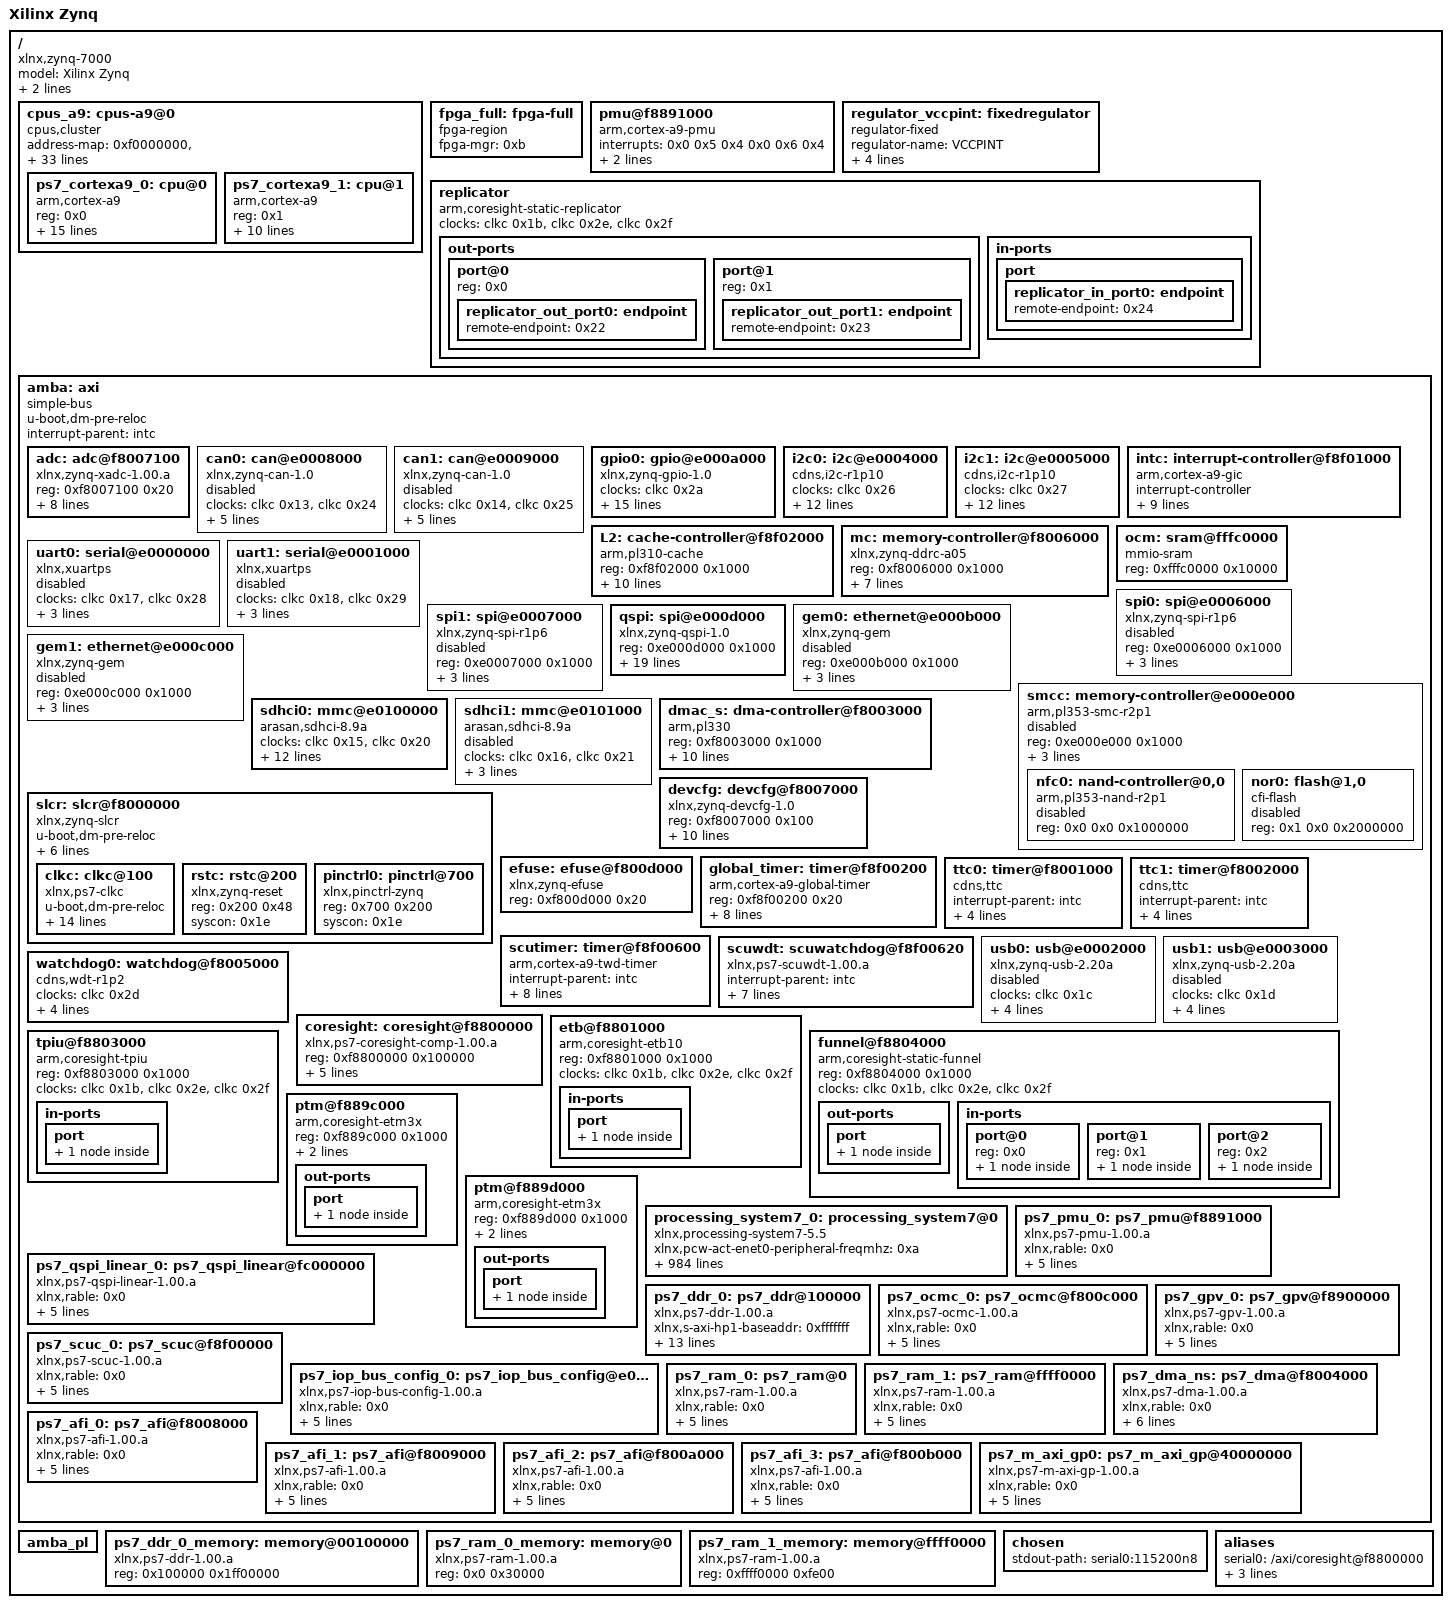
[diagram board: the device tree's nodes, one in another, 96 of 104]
/*
 * Copyright (C) 2011-2022 Xilinx, Inc.
 * Copyright (C) 2022 Advanced Micro Devices, Inc. All Rights Reserved.
 *
 * This software is licensed under the terms of the GNU General Public
 * License version 2, as published by the Free Software Foundation, and
 * may be copied, distributed, and modified under those terms.
 *
 * This program is distributed in the hope that it will be useful,
 * but WITHOUT ANY WARRANTY; without even the implied warranty of
 * MERCHANTABILITY or FITNESS FOR A PARTICULAR PURPOSE.  See the
 * GNU General Public License for more details.
 */

/dts-v1/;

/ {
        #address-cells = <0x1>;
        #size-cells = <0x1>;
        compatible = "xlnx,zynq-7000";
        model = "Xilinx Zynq";
        device_id = "7z010";
        slrcount = <0x1>;

        cpus_a9: cpus-a9@0 {
                #address-cells = <0x1>;
                #size-cells = <0x0>;
                compatible = "cpus,cluster";
                address-map = <0xf0000000 &amba 0xf0000000 0x10000000>,
                 <0x100000 &ps7_ddr_0_memory 0x100000 0x1ff00000>,
                 <0x0 &ps7_ram_0_memory 0x0 0x30000>,
                 <0xffff0000 &ps7_ram_1_memory 0xffff0000 0xfe00>,
                 <0xf8008000 &ps7_afi_0 0xf8008000 0x1000>,
                 <0xf8009000 &ps7_afi_1 0xf8009000 0x1000>,
                 <0xf800a000 &ps7_afi_2 0xf800a000 0x1000>,
                 <0xf800b000 &ps7_afi_3 0xf800b000 0x1000>,
                 <0xf8800000 &coresight 0xf8800000 0x100000>,
                 <0xf8006000 &mc 0xf8006000 0x1000>,
                 <0xf8007000 &devcfg 0xf8007000 0x100>,
                 <0xf8004000 &ps7_dma_ns 0xf8004000 0x1000>,
                 <0xf8003000 &dmac_s 0xf8003000 0x1000>,
                 <0xf8f00200 &global_timer 0xf8f00200 0x100>,
                 <0xe000a000 &gpio0 0xe000a000 0x1000>,
                 <0xf8900000 &ps7_gpv_0 0xf8900000 0x100000>,
                 <0xe0004000 &i2c0 0xe0004000 0x1000>,
                 <0xe0005000 &i2c1 0xe0005000 0x1000>,
                 <0xf8f01000 &intc 0xf8f01000 0x1000>,
                 <0xe0200000 &ps7_iop_bus_config_0 0xe0200000 0x1000>,
                 <0xf8f02000 &L2 0xf8f02000 0x1000>,
                 <0xf800c000 &ps7_ocmc_0 0xf800c000 0x1000>,
                 <0xf8891000 &ps7_pmu_0 0xf8891000 0x1000>,
                 <0xe000d000 &qspi 0xe000d000 0x1000>,
                 <0xfc000000 &ps7_qspi_linear_0 0xfc000000 0x1000000>,
                 <0xf8f00000 &ps7_scuc_0 0xf8f00000 0xfd>,
                 <0xf8f00600 &scutimer 0xf8f00600 0x20>,
                 <0xf8f00620 &scuwdt 0xf8f00620 0xe0>,
                 <0xe0100000 &sdhci0 0xe0100000 0x1000>,
                 <0xf8000000 &slcr 0xf8000000 0x1000>,
                 <0xf8007100 &adc 0xf8007100 0x21>;
                #ranges-address-cells = <0x1>;
                #ranges-size-cells = <0x1>;
                phandle = <0x2e>;

                ps7_cortexa9_0: cpu@0 {
                        compatible = "arm,cortex-a9";
                        device_type = "cpu";
                        reg = <0x0>;
                        clocks = <&clkc 0x3>;
                        clock-latency = <0x3e8>;
                        cpu0-supply = <0x21>;
                        operating-points = <0xa2c2b 0xf4240 0x51616 0xf4240>;
                        xlnx,rable = <0x0>;
                        xlnx,i-cache-size = <0x8000>;
                        xlnx,d-cache-line-size = <0x14>;
                        xlnx,i-cache-line-size = <0x14>;
                        xlnx,cpu-1x-clk-freq-hz = <0x69f6bcb>;
                        xlnx,ip-name = "ps7_cortexa9";
                        xlnx,num-cores = <0x2>;
                        xlnx,d-cache-size = <0x8000>;
                        xlnx,cpu-clk-freq-hz = <0x27bc86bf>;
                        bus-handle = <0x1>;
                        phandle = <0x2a>;
                };

                ps7_cortexa9_1: cpu@1 {
                        compatible = "arm,cortex-a9";
                        device_type = "cpu";
                        reg = <0x1>;
                        clocks = <&clkc 0x3>;
                        xlnx,rable = <0x0>;
                        xlnx,i-cache-size = <0x8000>;
                        xlnx,d-cache-line-size = <0x14>;
                        xlnx,i-cache-line-size = <0x14>;
                        xlnx,cpu-1x-clk-freq-hz = <0x69f6bcb>;
                        xlnx,ip-name = "ps7_cortexa9";
                        xlnx,d-cache-size = <0x8000>;
                        xlnx,cpu-clk-freq-hz = <0x27bc86bf>;
                        bus-handle = <0x1>;
                        phandle = <0x2c>;
                };
        };

        fpga_full: fpga-full {
                compatible = "fpga-region";
                fpga-mgr = <0xb>;
                #address-cells = <0x1>;
                #size-cells = <0x1>;
                ranges;
                phandle = <0x2f>;
        };

        pmu@f8891000 {
                compatible = "arm,cortex-a9-pmu";
                interrupts = <0x0 0x5 0x4 0x0 0x6 0x4>;
                interrupt-parent = <&intc>;
                reg = <0xf8891000 0x1000 0xf8893000 0x1000>;
        };

        regulator_vccpint: fixedregulator {
                compatible = "regulator-fixed";
                regulator-name = "VCCPINT";
                regulator-min-microvolt = <0xf4240>;
                regulator-max-microvolt = <0xf4240>;
                regulator-boot-on;
                regulator-always-on;
                phandle = <0x21>;
        };

        replicator {
                compatible = "arm,coresight-static-replicator";
                clocks = <&clkc 0x1b>,
                 <&clkc 0x2e>,
                 <&clkc 0x2f>;
                clock-names = "apb_pclk", "dbg_trc", "dbg_apb";

                out-ports {
                        #address-cells = <0x1>;
                        #size-cells = <0x0>;
                        /* replicator output ports */

                        port@0 {
                                reg = <0x0>;

                                replicator_out_port0: endpoint {
                                        remote-endpoint = <0x22>;
                                        phandle = <0x26>;
                                };
                        };

                        port@1 {
                                reg = <0x1>;

                                replicator_out_port1: endpoint {
                                        remote-endpoint = <0x23>;
                                        phandle = <0x25>;
                                };
                        };
                };

                in-ports {
                        /* replicator input port */

                        port {

                                replicator_in_port0: endpoint {
                                        remote-endpoint = <0x24>;
                                        phandle = <0x27>;
                                };
                        };
                };
        };

        amba: axi {
                u-boot,dm-pre-reloc;
                compatible = "simple-bus";
                #address-cells = <0x1>;
                #size-cells = <0x1>;
                interrupt-parent = <&intc>;
                ranges;
                phandle = <0x1>;

                adc: adc@f8007100 {
                        compatible = "xlnx,zynq-xadc-1.00.a";
                        reg = <0xf8007100 0x20>;
                        interrupts = <0x0 0x7 0x4>;
                        interrupt-parent = <&intc>;
                        clocks = <&clkc 0xc>;
                        xlnx,rable = <0x0>;
                        status = "okay";
                        xlnx,interconnect-s-axi-masters = "ps7_cortexa9_0.M_AXI_DP , & , ps7_cortexa9_1.M_AXI_DP";
                        xlnx,ip-name = "ps7_xadc";
                        xlnx,name = "ps7_xadc_0";
                        phandle = <0x1f>;
                };

                can0: can@e0008000 {
                        compatible = "xlnx,zynq-can-1.0";
                        status = "disabled";
                        clocks = <&clkc 0x13>,
                         <&clkc 0x24>;
                        clock-names = "can_clk", "pclk";
                        reg = <0xe0008000 0x1000>;
                        interrupts = <0x0 0x1c 0x4>;
                        interrupt-parent = <&intc>;
                        tx-fifo-depth = <0x40>;
                        rx-fifo-depth = <0x40>;
                        phandle = <0x30>;
                };

                can1: can@e0009000 {
                        compatible = "xlnx,zynq-can-1.0";
                        status = "disabled";
                        clocks = <&clkc 0x14>,
                         <&clkc 0x25>;
                        clock-names = "can_clk", "pclk";
                        reg = <0xe0009000 0x1000>;
                        interrupts = <0x0 0x33 0x4>;
                        interrupt-parent = <&intc>;
                        tx-fifo-depth = <0x40>;
                        rx-fifo-depth = <0x40>;
                        phandle = <0x31>;
                };

                gpio0: gpio@e000a000 {
                        compatible = "xlnx,zynq-gpio-1.0";
                        #gpio-cells = <0x2>;
                        clocks = <&clkc 0x2a>;
                        gpio-controller;
                        interrupt-controller;
                        #interrupt-cells = <0x2>;
                        interrupt-parent = <&intc>;
                        interrupts = <0x0 0x14 0x4>;
                        reg = <0xe000a000 0x1000>;
                        xlnx,rable = <0x0>;
                        xlnx,mio-gpio-mask = <0x5600>;
                        status = "okay";
                        gpio-mask-high = <0x0>;
                        xlnx,interconnect-s-axi-masters = "ps7_cortexa9_0.M_AXI_DP , & , ps7_cortexa9_1.M_AXI_DP";
                        xlnx,emio-gpio-width = <0x40>;
                        xlnx,ip-name = "ps7_gpio";
                        gpio-mask-low = <0x5600>;
                        emio-gpio-width = <0x40>;
                        xlnx,name = "ps7_gpio_0";
                        phandle = <0xf>;
                };

                i2c0: i2c@e0004000 {
                        compatible = "cdns,i2c-r1p10";
                        status = "okay";
                        clocks = <&clkc 0x26>;
                        clock-frequency = <0x61a80>;
                        interrupt-parent = <&intc>;
                        interrupts = <0x0 0x19 0x4>;
                        reg = <0xe0004000 0x1000>;
                        #address-cells = <0x1>;
                        #size-cells = <0x0>;
                        xlnx,rable = <0x0>;
                        xlnx,has-interrupt = <0x0>;
                        xlnx,clock-freq = <0x69f6bcb>;
                        xlnx,interconnect-s-axi-masters = "ps7_cortexa9_0.M_AXI_DP , & , ps7_cortexa9_1.M_AXI_DP";
                        xlnx,i2c-clk-freq-hz = <0x69f6bcb>;
                        xlnx,ip-name = "ps7_i2c";
                        xlnx,name = "ps7_i2c_0";
                        phandle = <0x11>;
                };

                i2c1: i2c@e0005000 {
                        compatible = "cdns,i2c-r1p10";
                        status = "okay";
                        clocks = <&clkc 0x27>;
                        clock-frequency = <0x61a80>;
                        interrupt-parent = <&intc>;
                        interrupts = <0x0 0x30 0x4>;
                        reg = <0xe0005000 0x1000>;
                        #address-cells = <0x1>;
                        #size-cells = <0x0>;
                        xlnx,rable = <0x0>;
                        xlnx,has-interrupt = <0x0>;
                        xlnx,clock-freq = <0x69f6bcb>;
                        xlnx,interconnect-s-axi-masters = "ps7_cortexa9_0.M_AXI_DP , & , ps7_cortexa9_1.M_AXI_DP";
                        xlnx,i2c-clk-freq-hz = <0x69f6bcb>;
                        xlnx,ip-name = "ps7_i2c";
                        xlnx,name = "ps7_i2c_1";
                        phandle = <0x12>;
                };

                intc: interrupt-controller@f8f01000 {
                        compatible = "arm,cortex-a9-gic";
                        #interrupt-cells = <0x3>;
                        interrupt-controller;
                        reg = <0xf8f01000 0x1000 0xf8f00100 0x100>;
                        xlnx,rable = <0x0>;
                        status = "okay";
                        xlnx,ppi-s-axi-baseaddr = <0xf8f01000>;
                        xlnx,irq-f2p-mode = "DIRECT";
                        xlnx,interconnect-s-axi-masters = "ps7_cortexa9_0.M_AXI_DP , & , ps7_cortexa9_1.M_AXI_DP";
                        xlnx,ip-name = "ps7_intc_dist";
                        xlnx,ppi-s-axi-highaddr = <0xf8f01fff>;
                        xlnx,name = "ps7_intc_dist_0";
                        phandle = <0x13>;
                };

                L2: cache-controller@f8f02000 {
                        compatible = "arm,pl310-cache";
                        reg = <0xf8f02000 0x1000>;
                        interrupts = <0x0 0x2 0x4>;
                        arm,data-latency = <0x3 0x2 0x2>;
                        arm,tag-latency = <0x2 0x2 0x2>;
                        cache-unified;
                        cache-level = <0x2>;
                        xlnx,rable = <0x0>;
                        status = "okay";
                        xlnx,interconnect-s-axi-masters = "ps7_cortexa9_0.M_AXI_DP , & , ps7_cortexa9_1.M_AXI_DP";
                        xlnx,ip-name = "ps7_pl310";
                        xlnx,name = "ps7_pl310_0";
                        phandle = <0x15>;
                };

                mc: memory-controller@f8006000 {
                        compatible = "xlnx,zynq-ddrc-a05";
                        reg = <0xf8006000 0x1000>;
                        xlnx,rable = <0x0>;
                        status = "okay";
                        xlnx,interconnect-s-axi-masters = "ps7_cortexa9_0.M_AXI_DP , & , ps7_cortexa9_1.M_AXI_DP";
                        xlnx,ddr-clk-freq-hz = <0x1fca057e>;
                        xlnx,ip-name = "ps7_ddrc";
                        xlnx,has-ecc = <0x0>;
                        xlnx,name = "ps7_ddrc_0";
                        phandle = <0xa>;
                };

                ocm: sram@fffc0000 {
                        compatible = "mmio-sram";
                        reg = <0xfffc0000 0x10000>;
                        phandle = <0x32>;
                };

                uart0: serial@e0000000 {
                        compatible = "xlnx,xuartps", "cdns,uart-r1p8";
                        status = "disabled";
                        clocks = <&clkc 0x17>,
                         <&clkc 0x28>;
                        clock-names = "uart_clk", "pclk";
                        reg = <0xe0000000 0x1000>;
                        interrupts = <0x0 0x1b 0x4>;
                        interrupt-parent = <&intc>;
                        phandle = <0x33>;
                };

                uart1: serial@e0001000 {
                        compatible = "xlnx,xuartps", "cdns,uart-r1p8";
                        status = "disabled";
                        clocks = <&clkc 0x18>,
                         <&clkc 0x29>;
                        clock-names = "uart_clk", "pclk";
                        reg = <0xe0001000 0x1000>;
                        interrupts = <0x0 0x32 0x4>;
                        interrupt-parent = <&intc>;
                        phandle = <0x34>;
                };

                spi0: spi@e0006000 {
                        compatible = "xlnx,zynq-spi-r1p6";
                        reg = <0xe0006000 0x1000>;
                        status = "disabled";
                        interrupt-parent = <&intc>;
                        interrupts = <0x0 0x1a 0x4>;
                        clocks = <&clkc 0x19>,
                         <&clkc 0x22>;
                        clock-names = "ref_clk", "pclk";
                        #address-cells = <0x1>;
                        #size-cells = <0x0>;
                        phandle = <0x35>;
                };

                spi1: spi@e0007000 {
                        compatible = "xlnx,zynq-spi-r1p6";
                        reg = <0xe0007000 0x1000>;
                        status = "disabled";
                        interrupt-parent = <&intc>;
                        interrupts = <0x0 0x31 0x4>;
                        clocks = <&clkc 0x1a>,
                         <&clkc 0x23>;
                        clock-names = "ref_clk", "pclk";
                        #address-cells = <0x1>;
                        #size-cells = <0x0>;
                        phandle = <0x36>;
                };

                qspi: spi@e000d000 {
                        compatible = "xlnx,zynq-qspi-1.0";
                        reg = <0xe000d000 0x1000>;
                        interrupt-parent = <&intc>;
                        interrupts = <0x0 0x13 0x4>;
                        clocks = <&clkc 0xa>,
                         <&clkc 0x2b>;
                        clock-names = "ref_clk", "pclk";
                        status = "okay";
                        #address-cells = <0x1>;
                        #size-cells = <0x0>;
                        xlnx,qspi-clk-freq-hz = <0xbebc200>;
                        xlnx,rable = <0x0>;
                        xlnx,bus-width = <0x2>;
                        xlnx,ip-name = "ps7_qspi";
                        xlnx,interconnect-s-axi-masters = "ps7_cortexa9_0.M_AXI_DP , & , ps7_cortexa9_1.M_AXI_DP";
                        spi-rx-bus-width = <0x4>;
                        xlnx,connection-mode = <0x0>;
                        spi-tx-bus-width = <0x4>;
                        qspi-fbclk = <0x0>;
                        xlnx,clock-freq = <0xbebc200>;
                        xlnx,fb-clk = <0x0>;
                        xlnx,qspi-mode = <0x0>;
                        xlnx,name = "ps7_qspi_0";
                        xlnx,qspi-bus-width = <0x2>;
                        is-dual = <0x0>;
                        phandle = <0x18>;
                };

                gem0: ethernet@e000b000 {
                        compatible = "xlnx,zynq-gem", "cdns,gem";
                        reg = <0xe000b000 0x1000>;
                        status = "disabled";
                        interrupts = <0x0 0x16 0x4>;
                        interrupt-parent = <&intc>;
                        clocks = <&clkc 0x1e>,
                         <&clkc 0x1e>,
                         <&clkc 0xd>;
                        clock-names = "pclk", "hclk", "tx_clk";
                        #address-cells = <0x1>;
                        #size-cells = <0x0>;
                        phandle = <0x37>;
                };

                gem1: ethernet@e000c000 {
                        compatible = "xlnx,zynq-gem", "cdns,gem";
                        reg = <0xe000c000 0x1000>;
                        status = "disabled";
                        interrupts = <0x0 0x2d 0x4>;
                        interrupt-parent = <&intc>;
                        clocks = <&clkc 0x1f>,
                         <&clkc 0x1f>,
                         <&clkc 0xe>;
                        clock-names = "pclk", "hclk", "tx_clk";
                        #address-cells = <0x1>;
                        #size-cells = <0x0>;
                        phandle = <0x38>;
                };

                smcc: memory-controller@e000e000 {
                        compatible = "arm,pl353-smc-r2p1", "arm,primecell";
                        reg = <0xe000e000 0x1000>;
                        status = "disabled";
                        clock-names = "memclk", "apb_pclk";
                        clocks = <&clkc 0xb>,
                         <&clkc 0x2c>;
                        ranges = <0x0 0x0 0xe1000000 0x1000000 0x1 0x0 0xe2000000 0x2000000 0x2 0x0 0xe4000000 0x2000000>;
                        /* SRAM/NOR CS1 region */
                        #address-cells = <0x2>;
                        #size-cells = <0x1>;
                        interrupt-parent = <&intc>;
                        interrupts = <0x0 0x12 0x4>;
                        phandle = <0x39>;

                        nfc0: nand-controller@0,0 {
                                compatible = "arm,pl353-nand-r2p1";
                                reg = <0x0 0x0 0x1000000>;
                                status = "disabled";
                                #address-cells = <0x1>;
                                #size-cells = <0x0>;
                                phandle = <0x3a>;
                        };

                        nor0: flash@1,0 {
                                status = "disabled";
                                compatible = "cfi-flash";
                                reg = <0x1 0x0 0x2000000>;
                                #address-cells = <0x1>;
                                #size-cells = <0x1>;
                                phandle = <0x3b>;
                        };
                };

                sdhci0: mmc@e0100000 {
                        compatible = "arasan,sdhci-8.9a";
                        status = "okay";
                        clock-names = "clk_xin", "clk_ahb";
                        clocks = <&clkc 0x15>,
                         <&clkc 0x20>;
                        interrupt-parent = <&intc>;
                        interrupts = <0x0 0x18 0x4>;
                        reg = <0xe0100000 0x1000>;
                        xlnx,rable = <0x0>;
                        xlnx,has-power = <0x0>;
                        xlnx,interconnect-s-axi-masters = "ps7_cortexa9_0.M_AXI_DP , & , ps7_cortexa9_1.M_AXI_DP";
                        xlnx,ip-name = "ps7_sdio";
                        xlnx,sdio-clk-freq-hz = <0x5f5e100>;
                        xlnx,has-wp = <0x0>;
                        xlnx,has-cd = <0x0>;
                        xlnx,name = "ps7_sd_0";
                        phandle = <0x1d>;
                };

                sdhci1: mmc@e0101000 {
                        compatible = "arasan,sdhci-8.9a";
                        status = "disabled";
                        clock-names = "clk_xin", "clk_ahb";
                        clocks = <&clkc 0x16>,
                         <&clkc 0x21>;
                        interrupt-parent = <&intc>;
                        interrupts = <0x0 0x2f 0x4>;
                        reg = <0xe0101000 0x1000>;
                        phandle = <0x3c>;
                };

                slcr: slcr@f8000000 {
                        u-boot,dm-pre-reloc;
                        #address-cells = <0x1>;
                        #size-cells = <0x1>;
                        compatible = "xlnx,zynq-slcr", "syscon", "simple-mfd";
                        reg = <0xf8000000 0x1000>;
                        ranges;
                        xlnx,rable = <0x0>;
                        status = "okay";
                        xlnx,interconnect-s-axi-masters = "ps7_cortexa9_0.M_AXI_DP , & , ps7_cortexa9_1.M_AXI_DP";
                        xlnx,ip-name = "ps7_slcr";
                        xlnx,name = "ps7_slcr_0";
                        phandle = <0x1e>;

                        clkc: clkc@100 {
                                u-boot,dm-pre-reloc;
                                #clock-cells = <0x1>;
                                compatible = "xlnx,ps7-clkc";
                                fclk-enable = <0x1>;
                                clock-output-names = "armpll", "ddrpll", "iopll", "cpu_6or4x", "cpu_3or2x", "cpu_2x", "cpu_1x", "ddr2x", "ddr3x", "dci", "lqspi", "smc", "pcap", "gem0", "gem1", "fclk0", "fclk1", "fclk2", "fclk3", "can0", "can1", "sdio0", "sdio1", "uart0", "uart1", "spi0", "spi1", "dma", "usb0_aper", "usb1_aper", "gem0_aper", "gem1_aper", "sdio0_aper", "sdio1_aper", "spi0_aper", "spi1_aper", "can0_aper", "can1_aper", "i2c0_aper", "i2c1_aper", "uart0_aper", "uart1_aper", "gpio_aper", "lqspi_aper", "smc_aper", "swdt", "dbg_trc", "dbg_apb";
                                reg = <0x100 0x100>;
                                ps-clk-frequency = <0x1fca055>;
                                phandle = <0x20>;
                        };

                        rstc: rstc@200 {
                                compatible = "xlnx,zynq-reset";
                                reg = <0x200 0x48>;
                                #reset-cells = <0x1>;
                                syscon = <0x1e>;
                                phandle = <0x3d>;
                        };

                        pinctrl0: pinctrl@700 {
                                compatible = "xlnx,pinctrl-zynq";
                                reg = <0x700 0x200>;
                                syscon = <0x1e>;
                                phandle = <0x3e>;
                        };
                };

                dmac_s: dma-controller@f8003000 {
                        compatible = "arm,pl330", "arm,primecell";
                        reg = <0xf8003000 0x1000>;
                        interrupt-parent = <&intc>;
                        /*
                         * interrupt-names = "abort", "dma0", "dma1", "dma2", "dma3",
                         * "dma4", "dma5", "dma6", "dma7";
                         */
                        interrupts = <0x0 0xd 0x4 0x0 0xe 0x4 0x0 0xf 0x4 0x0 0x10 0x4 0x0 0x11 0x4 0x0 0x28 0x4 0x0 0x29 0x4 0x0 0x2a 0x4 0x0 0x2b 0x4>;
                        #dma-cells = <0x1>;
                        clocks = <&clkc 0x1b>;
                        clock-names = "apb_pclk";
                        xlnx,rable = <0x0>;
                        status = "okay";
                        xlnx,interconnect-s-axi-masters = "ps7_cortexa9_0.M_AXI_DP , & , ps7_cortexa9_1.M_AXI_DP";
                        xlnx,ip-name = "ps7_dma";
                        xlnx,is-secure;
                        xlnx,name = "ps7_dma_s";
                        phandle = <0xd>;
                };

                devcfg: devcfg@f8007000 {
                        compatible = "xlnx,zynq-devcfg-1.0";
                        reg = <0xf8007000 0x100>;
                        interrupt-parent = <&intc>;
                        interrupts = <0x0 0x8 0x4>;
                        clocks = <&clkc 0xc>,
                         <&clkc 0xf>,
                         <&clkc 0x10>,
                         <&clkc 0x11>,
                         <&clkc 0x12>;
                        clock-names = "ref_clk", "fclk0", "fclk1", "fclk2", "fclk3";
                        syscon = <0x1e>;
                        xlnx,rable = <0x0>;
                        status = "okay";
                        xlnx,interconnect-s-axi-masters = "ps7_cortexa9_0.M_AXI_DP , & , ps7_cortexa9_1.M_AXI_DP";
                        xlnx,ip-name = "ps7_dev_cfg";
                        xlnx,name = "ps7_dev_cfg_0";
                        phandle = <0xb>;
                };

                efuse: efuse@f800d000 {
                        compatible = "xlnx,zynq-efuse";
                        reg = <0xf800d000 0x20>;
                        phandle = <0x3f>;
                };

                global_timer: timer@f8f00200 {
                        compatible = "arm,cortex-a9-global-timer";
                        reg = <0xf8f00200 0x20>;
                        interrupts = <0x1 0xb 0x301>;
                        interrupt-parent = <&intc>;
                        clocks = <&clkc 0x4>;
                        xlnx,rable = <0x0>;
                        status = "okay";
                        xlnx,interconnect-s-axi-masters = "ps7_cortexa9_0.M_AXI_DP , & , ps7_cortexa9_1.M_AXI_DP";
                        xlnx,ip-name = "ps7_globaltimer";
                        xlnx,name = "ps7_globaltimer_0";
                        phandle = <0xe>;
                };

                ttc0: timer@f8001000 {
                        interrupt-parent = <&intc>;
                        interrupts = <0x0 0xa 0x4 0x0 0xb 0x4 0x0 0xc 0x4>;
                        compatible = "cdns,ttc";
                        clocks = <&clkc 0x6>;
                        reg = <0xf8001000 0x1000>;
                        phandle = <0x40>;
                };

                ttc1: timer@f8002000 {
                        interrupt-parent = <&intc>;
                        interrupts = <0x0 0x25 0x4 0x0 0x26 0x4 0x0 0x27 0x4>;
                        compatible = "cdns,ttc";
                        clocks = <&clkc 0x6>;
                        reg = <0xf8002000 0x1000>;
                        phandle = <0x41>;
                };

                scutimer: timer@f8f00600 {
                        interrupt-parent = <&intc>;
                        interrupts = <0x1 0xd 0x301>;
                        compatible = "arm,cortex-a9-twd-timer";
                        reg = <0xf8f00600 0x20>;
                        clocks = <&clkc 0x4>;
                        xlnx,rable = <0x0>;
                        status = "okay";
                        xlnx,interconnect-s-axi-masters = "ps7_cortexa9_0.M_AXI_DP , & , ps7_cortexa9_1.M_AXI_DP";
                        xlnx,ip-name = "ps7_scutimer";
                        xlnx,name = "ps7_scutimer_0";
                        phandle = <0x1b>;
                };

                scuwdt: scuwatchdog@f8f00620 {
                        interrupt-parent = <&intc>;
                        interrupts = <0x1 0xe 0x4>;
                        compatible = "xlnx,ps7-scuwdt-1.00.a";
                        reg = <0xf8f00620 0xe0>;
                        xlnx,rable = <0x0>;
                        status = "okay";
                        xlnx,interconnect-s-axi-masters = "ps7_cortexa9_0.M_AXI_DP , & , ps7_cortexa9_1.M_AXI_DP";
                        xlnx,ip-name = "ps7_scuwdt";
                        xlnx,name = "ps7_scuwdt_0";
                        phandle = <0x1c>;
                };

                usb0: usb@e0002000 {
                        compatible = "xlnx,zynq-usb-2.20a", "chipidea,usb2";
                        status = "disabled";
                        clocks = <&clkc 0x1c>;
                        interrupt-parent = <&intc>;
                        interrupts = <0x0 0x15 0x4>;
                        reg = <0xe0002000 0x1000>;
                        phy_type = "ulpi";
                        phandle = <0x42>;
                };

                usb1: usb@e0003000 {
                        compatible = "xlnx,zynq-usb-2.20a", "chipidea,usb2";
                        status = "disabled";
                        clocks = <&clkc 0x1d>;
                        interrupt-parent = <&intc>;
                        interrupts = <0x0 0x2c 0x4>;
                        reg = <0xe0003000 0x1000>;
                        phy_type = "ulpi";
                        phandle = <0x43>;
                };

                watchdog0: watchdog@f8005000 {
                        clocks = <&clkc 0x2d>;
                        compatible = "cdns,wdt-r1p2";
                        interrupt-parent = <&intc>;
                        interrupts = <0x0 0x9 0x1>;
                        reg = <0xf8005000 0x1000>;
                        timeout-sec = <0xa>;
                        phandle = <0x44>;
                };

                coresight: coresight@f8800000 {
                        compatible = "xlnx,ps7-coresight-comp-1.00.a";
                        status = "okay";
                        reg = <0xf8800000 0x100000>;
                        xlnx,rable = <0x0>;
                        xlnx,interconnect-s-axi-masters = "ps7_cortexa9_0.M_AXI_DP , & , ps7_cortexa9_1.M_AXI_DP";
                        xlnx,ip-name = "ps7_coresight_comp";
                        xlnx,name = "ps7_coresight_comp_0";
                        phandle = <0x9>;
                };

                etb@f8801000 {
                        compatible = "arm,coresight-etb10", "arm,primecell";
                        reg = <0xf8801000 0x1000>;
                        clocks = <&clkc 0x1b>,
                         <&clkc 0x2e>,
                         <&clkc 0x2f>;
                        clock-names = "apb_pclk", "dbg_trc", "dbg_apb";

                        in-ports {

                                port {

                                        etb_in_port: endpoint {
                                                remote-endpoint = <0x25>;
                                                phandle = <0x23>;
                                        };
                                };
                        };
                };

                tpiu@f8803000 {
                        compatible = "arm,coresight-tpiu", "arm,primecell";
                        reg = <0xf8803000 0x1000>;
                        clocks = <&clkc 0x1b>,
                         <&clkc 0x2e>,
                         <&clkc 0x2f>;
                        clock-names = "apb_pclk", "dbg_trc", "dbg_apb";

                        in-ports {

                                port {

                                        tpiu_in_port: endpoint {
                                                remote-endpoint = <0x26>;
                                                phandle = <0x22>;
                                        };
                                };
                        };
                };

                funnel@f8804000 {
                        compatible = "arm,coresight-static-funnel", "arm,primecell";
                        reg = <0xf8804000 0x1000>;
                        clocks = <&clkc 0x1b>,
                         <&clkc 0x2e>,
                         <&clkc 0x2f>;
                        clock-names = "apb_pclk", "dbg_trc", "dbg_apb";
                        /* funnel output ports */

                        out-ports {

                                port {

                                        funnel_out_port: endpoint {
                                                remote-endpoint = <0x27>;
                                                phandle = <0x24>;
                                        };
                                };
                        };

                        in-ports {
                                #address-cells = <0x1>;
                                #size-cells = <0x0>;
                                /* funnel input ports */

                                port@0 {
                                        reg = <0x0>;

                                        funnel0_in_port0: endpoint {
                                                remote-endpoint = <0x28>;
                                                phandle = <0x2b>;
                                        };
                                };

                                port@1 {
                                        reg = <0x1>;

                                        funnel0_in_port1: endpoint {
                                                remote-endpoint = <0x29>;
                                                phandle = <0x2d>;
                                        };
                                };

                                port@2 {
                                        reg = <0x2>;

                                        funnel0_in_port2: endpoint {
                                                phandle = <0x45>;
                                        };
                                };
                        };
                };

                ptm@f889c000 {
                        compatible = "arm,coresight-etm3x", "arm,primecell";
                        reg = <0xf889c000 0x1000>;
                        clocks = <&clkc 0x1b>,
                         <&clkc 0x2e>,
                         <&clkc 0x2f>;
                        clock-names = "apb_pclk", "dbg_trc", "dbg_apb";
                        cpu = <0x2a>;

                        out-ports {

                                port {

                                        ptm0_out_port: endpoint {
                                                remote-endpoint = <0x2b>;
                                                phandle = <0x28>;
                                        };
                                };
                        };
                };

                ptm@f889d000 {
                        compatible = "arm,coresight-etm3x", "arm,primecell";
                        reg = <0xf889d000 0x1000>;
                        clocks = <&clkc 0x1b>,
                         <&clkc 0x2e>,
                         <&clkc 0x2f>;
                        clock-names = "apb_pclk", "dbg_trc", "dbg_apb";
                        cpu = <0x2c>;

                        out-ports {

                                port {

                                        ptm1_out_port: endpoint {
                                                remote-endpoint = <0x2d>;
                                                phandle = <0x29>;
                                        };
                                };
                        };
                };

                processing_system7_0: processing_system7@0 {
                        xlnx,pcw-act-enet0-peripheral-freqmhz = <0xa>;
                        xlnx,pcw-nor-grp-sram-cs1-io = "<Select>";
                        xlnx,num-f2p-intr-inputs = <0x1>;
                        reg = <0x0 0x20000000>;
                        xlnx,pcw-mio-18-direction = "inout";
                        xlnx,pcw-nand-cycles-t-ar = <0x1>;
                        xlnx,pcw-p2f-dmac7-intr = <0x0>;
                        xlnx,pcw-en-clk1-port = <0x1>;
                        xlnx,pcw-crystal-peripheral-freqmhz = <0x1fca055>;
                        xlnx,pcw-nor-grp-sram-cs1-enable = <0x0>;
                        xlnx,pcw-uiparam-ddr-dq-1-package-length = <0x4366e20>;
                        xlnx,pcw-act-wdt-peripheral-freqmhz = <0x69f6bcb>;
                        xlnx,pcw-p2f-dmac4-intr = <0x0>;
                        xlnx,pcw-s-axi-hp3-id-width = <0x6>;
                        xlnx,pcw-en-emio-uart0 = <0x0>;
                        xlnx,pcw-en-emio-uart1 = <0x0>;
                        xlnx,pcw-ddr-hpr-to-critical-priority-level = <0xf>;
                        xlnx,pcw-enet-reset-polarity = "Active , Low";
                        xlnx,pcw-mio-5-direction = "inout";
                        xlnx,pcw-p2f-dmac1-intr = <0x0>;
                        xlnx,pcw-sd0-grp-cd-enable = <0x0>;
                        xlnx,pcw-act-fpga1-peripheral-freqmhz = <0x20>;
                        xlnx,pcw-mio-24-iotype = "LVCMOS , 3.3V";
                        xlnx,pcw-ddr-port1-hpr-enable = <0x0>;
                        xlnx,pcw-cpu-peripheral-clksrc = "ARM , PLL";
                        xlnx,pcw-mio-53-pullup = "enabled";
                        xlnx,pcw-use-axi-nonsecure = <0x0>;
                        xlnx,pcw-spi1-grp-ss0-io = "<Select>";
                        xlnx,pcw-uiparam-ddr-dqs-1-propogation-delay = <0xa0>;
                        xlnx,pcw-nor-cs1-t-pc = <0x1>;
                        xlnx,pcw-s-axi-gp0-id-width = <0x6>;
                        xlnx,pcw-trace-grp-8bit-io = "<Select>";
                        xlnx,pcw-ttc-peripheral-freqmhz = <0x32>;
                        xlnx,pcw-uart0-baseaddr = <0xe0000000>;
                        xlnx,pcw-ftm-cti-out0 = "DISABLED";
                        xlnx,pcw-ttc1-clk0-peripheral-divisor0 = <0x1>;
                        xlnx,pcw-uiparam-ddr-clock-stop-en = <0x0>;
                        xlnx,pcw-ftm-cti-out1 = "DISABLED";
                        xlnx,pcw-mio-28-direction = "inout";
                        xlnx,pcw-en-ttc0 = <0x0>;
                        xlnx,pcw-ftm-cti-out2 = "DISABLED";
                        xlnx,pcw-mio-11-pullup = "enabled";
                        xlnx,pcw-en-ttc1 = <0x0>;
                        xlnx,pcw-ftm-cti-out3 = "DISABLED";
                        xlnx,pcw-m-axi-gp0-thread-id-width = <0xc>;
                        xlnx,pcw-nor-sram-cs1-t-ceoe = <0x1>;
                        xlnx,pcw-nor-grp-sram-int-enable = <0x0>;
                        xlnx,pcw-can-peripheral-clksrc = "IO , PLL";
                        xlnx,pcw-ttc1-clk0-peripheral-clksrc = "CPU_1X";
                        xlnx,mio-primitive = <0x36>;
                        xlnx,pcw-gp0-num-write-threads = <0x4>;
                        xlnx,pcw-mio-4-iotype = "LVCMOS , 3.3V";
                        xlnx,pcw-mio-41-iotype = "LVCMOS , 3.3V";
                        xlnx,pcw-nor-cs1-t-rc = <0xb>;
                        xlnx,pcw-i2c0-grp-int-enable = <0x0>;
                        xlnx,pcw-ddr-port2-hpr-enable = <0x0>;
                        xlnx,pcw-act-tpiu-peripheral-freqmhz = <0xc8>;
                        xlnx,pcw-package-name = "clg400";
                        xlnx,pcw-s-axi-hp0-id-width = <0x6>;
                        xlnx,pcw-package-ddr-dqs-to-clk-delay-0 = <0x153d8>;
                        xlnx,pcw-uiparam-ddr-dqs-3-length-mm = <0x0>;
                        xlnx,pcw-package-ddr-dqs-to-clk-delay-1 = <0x29810>;
                        xlnx,pcw-qspi-grp-single-ss-enable = <0x1>;
                        xlnx,pcw-act-usb0-peripheral-freqmhz = <0x3c>;
                        xlnx,pcw-mio-27-pullup = "enabled";
                        xlnx,pcw-package-ddr-dqs-to-clk-delay-2 = <0x3a980>;
                        xlnx,pcw-sdio0-baseaddr = <0xe0100000>;
                        xlnx,pcw-mio-38-direction = "inout";
                        xlnx,pcw-package-ddr-dqs-to-clk-delay-3 = <0x37aa0>;
                        xlnx,pcw-en-spi0 = <0x0>;
                        xlnx,pcw-en-spi1 = <0x0>;
                        xlnx,pcw-include-acp-trans-check = <0x0>;
                        xlnx,pcw-ttc1-clk1-peripheral-divisor0 = <0x1>;
                        xlnx,en-emio-pjtag = <0x0>;
                        xlnx,pcw-nor-sram-cs0-we-time = <0x0>;
                        xlnx,pcw-uiparam-ddr-speed-bin = "DDR3_1066F";
                        xlnx,pcw-ddr-port3-hpr-enable = <0x0>;
                        xlnx,pcw-irq-f2p-intr = <0x0>;
                        xlnx,pcw-trace-peripheral-enable = <0x0>;
                        xlnx,pcw-enet0-grp-mdio-io = "<Select>";
                        xlnx,pcw-mio-15-iotype = "LVCMOS , 3.3V";
                        xlnx,pcw-nor-cs1-t-tr = <0x1>;
                        xlnx,pcw-mio-7-pullup = "disabled";
                        xlnx,pcw-mio-44-pullup = "enabled";
                        xlnx,pcw-uiparam-act-ddr-freq-mhz = <0x1fca057e>;
                        xlnx,pcw-use-ps-slcr-registers = <0x0>;
                        xlnx,pcw-mio-48-direction = "inout";
                        xlnx,pcw-ttc0-clk0-peripheral-divisor0 = <0x1>;
                        xlnx,pcw-trace-grp-4bit-io = "<Select>";
                        xlnx,pcw-nor-cs1-t-wc = <0xb>;
                        xlnx,pcw-gpio-peripheral-enable = <0x0>;
                        xlnx,pcw-nor-cs0-t-ceoe = <0x1>;
                        xlnx,pcw-spi-peripheral-clksrc = "IO , PLL";
                        xlnx,pcw-p2f-i2c0-intr = <0x0>;
                        xlnx,pcw-uiparam-ddr-clock-2-package-length = <0x34090b8>;
                        status = "okay";
                        xlnx,pcw-act-can-peripheral-freqmhz = <0xa>;
                        xlnx,pcw-ttc1-clk2-peripheral-divisor0 = <0x1>;
                        xlnx,pcw-mio-32-iotype = "LVCMOS , 3.3V";
                        xlnx,pcw-p2f-gpio-intr = <0x0>;
                        xlnx,pcw-ttc0-clk1-peripheral-freqmhz = <0x7f28155>;
                        xlnx,pcw-value-silversion = <0x3>;
                        xlnx,pcw-nor-cs1-t-wp = <0x1>;
                        xlnx,pcw-pcap-peripheral-divisor0 = <0x8>;
                        xlnx,pcw-spi1-spi1-io = "<Select>";
                        xlnx,pcw-can0-baseaddr = <0xe0008000>;
                        xlnx,pcw-wdt-peripheral-freqmhz = <0x7f28155>;
                        xlnx,pcw-mio-18-pullup = "enabled";
                        xlnx,pcw-uart1-baud-rate = <0x1c200>;
                        xlnx,pcw-mio-17-direction = "inout";
                        xlnx,pcw-trace-grp-2bit-io = "<Select>";
                        xlnx,pcw-ttc0-clk1-peripheral-divisor0 = <0x1>;
                        xlnx,pcw-spi0-grp-ss2-enable = <0x0>;
                        xlnx,pcw-mio-48-iotype = "LVCMOS , 3.3V";
                        xlnx,pcw-usb1-baseaddr = <0xe0103000>;
                        xlnx,pcw-gp1-num-read-threads = <0x4>;
                        xlnx,pcw-i2c1-highaddr = <0xe0005fff>;
                        xlnx,pcw-i2c1-i2c1-io = "MIO , 52 , .. , 53";
                        xlnx,pcw-sd0-sd0-io = "MIO , 40 , .. , 45";
                        xlnx,pcw-can0-grp-clk-enable = <0x0>;
                        xlnx,pcw-mio-4-direction = "inout";
                        xlnx,pcw-use-s-axi-acp = <0x0>;
                        xlnx,pcw-uart-peripheral-freqmhz = <0x64>;
                        xlnx,pcw-mio-35-pullup = "enabled";
                        xlnx,pcw-usb0-highaddr = <0xe0102fff>;
                        xlnx,pcw-gpio-baseaddr = <0xe000a000>;
                        xlnx,pcw-uiparam-ddr-partno = "MT41K256M16 , RE-125";
                        xlnx,pcw-qspi-peripheral-freqmhz = <0xc8>;
                        xlnx,pcw-mio-27-direction = "inout";
                        xlnx,pcw-mio-52-slew = "slow";
                        xlnx,pcw-can0-peripheral-clksrc = "External";
                        xlnx,pcw-uiparam-ddr-dram-width = "16 , Bits";
                        xlnx,pcw-nand-cycles-t-rc = <0xb>;
                        xlnx,pcw-nand-nand-io = "<Select>";
                        xlnx,pcw-nor-grp-sram-cs0-enable = <0x0>;
                        xlnx,pcw-clk1-freq = <0x1e84800>;
                        xlnx,pcw-mio-48-slew = "slow";
                        xlnx,pcw-m-axi-gp0-freqmhz = <0x32>;
                        xlnx,pcw-ttc0-clk2-peripheral-divisor0 = <0x1>;
                        xlnx,pcw-mio-45-slew = "slow";
                        xlnx,pcw-ttc1-highaddr = <0xe0105fff>;
                        xlnx,pcw-mio-23-iotype = "LVCMOS , 3.3V";
                        xlnx,pcw-mio-42-slew = "slow";
                        xlnx,pcw-mio-52-pullup = "enabled";
                        xlnx,m-axi-gp1-id-width = <0xc>;
                        xlnx,pcw-fclk-clk1-buf;
                        xlnx,pcw-dual-parallel-qspi-data-mode = "<Select>";
                        xlnx,pcw-nand-cycles-t-rr = <0x1>;
                        xlnx,pcw-en-rst1-port = <0x0>;
                        xlnx,pcw-mio-38-slew = "slow";
                        xlnx,pcw-uiparam-ddr-dqs-2-length-mm = <0x0>;
                        xlnx,pcw-mio-10-pullup = "enabled";
                        xlnx,pcw-mio-35-slew = "slow";
                        xlnx,pcw-mio-37-direction = "inout";
                        xlnx,pcw-nor-sram-cs0-t-ceoe = <0x1>;
                        xlnx,pcw-usb0-usb0-io = "<Select>";
                        xlnx,pcw-mio-32-slew = "slow";
                        xlnx,pcw-usb1-reset-io = "<Select>";
                        xlnx,pcw-enet1-peripheral-freqmhz = "1000 , Mbps";
                        xlnx,pcw-uiparam-ddr-clock-2-propogation-delay = <0xa0>;
                        xlnx,pcw-qspi-grp-single-ss-io = "MIO , 1 , .. , 6";
                        xlnx,pcw-mio-28-slew = "slow";
                        xlnx,pcw-mio-3-iotype = "LVCMOS , 3.3V";
                        xlnx,pcw-mio-39-iotype = "LVCMOS , 3.3V";
                        xlnx,pcw-mio-40-iotype = "LVCMOS , 3.3V";
                        xlnx,pcw-nor-cs1-we-time = <0x0>;
                        xlnx,pcw-enet1-reset-enable = <0x0>;
                        xlnx,pcw-mio-25-slew = "slow";
                        xlnx,pcw-can0-grp-clk-io = "<Select>";
                        xlnx,pcw-spi1-highaddr = <0xe0007fff>;
                        xlnx,pcw-uiparam-ddr-dq-3-length-mm = <0x0>;
                        xlnx,pcw-mio-22-slew = "slow";
                        xlnx,pcw-mio-26-pullup = "enabled";
                        xlnx,pcw-nand-cycles-t-wc = <0xb>;
                        xlnx,pcw-fpga2-peripheral-freqmhz = <0x78>;
                        xlnx,pcw-mio-18-slew = "slow";
                        xlnx,pcw-mio-47-direction = "inout";
                        xlnx,pcw-nor-sram-cs0-t-pc = <0x1>;
                        xlnx,pcw-can-peripheral-freqmhz = <0x64>;
                        xlnx,pcw-uiparam-ddr-dq-2-package-length = <0x386bb9c>;
                        xlnx,pcw-mio-15-slew = "slow";
                        xlnx,s-axi-hp0-data-width = <0x40>;
                        xlnx,emio-gpio-width = <0x40>;
                        xlnx,fclk-clk2-buf;
                        xlnx,pcw-mio-12-slew = "slow";
                        xlnx,pcw-en-emio-wdt = <0x0>;
                        xlnx,pcw-nand-cycles-t-wp = <0x1>;
                        xlnx,pcw-ttc1-clk0-peripheral-freqmhz = <0x7f28155>;
                        xlnx,pcw-ddr-ddr-pll-freqmhz = <0x3f940bf7>;
                        xlnx,pcw-enet0-reset-enable = <0x0>;
                        xlnx,pcw-preset-bank1-voltage = "LVCMOS , 3.3V";
                        xlnx,pcw-can1-grp-clk-io = "<Select>";
                        xlnx,pcw-nor-sram-cs0-t-rc = <0xb>;
                        xlnx,pcw-mio-14-iotype = "LVCMOS , 3.3V";
                        xlnx,pcw-mio-6-pullup = "disabled";
                        xlnx,pcw-enet-reset-enable = <0x0>;
                        xlnx,pcw-mio-43-pullup = "enabled";
                        xlnx,pcw-spi0-peripheral-enable = <0x0>;
                        xlnx,pcw-act-ttc0-clk0-peripheral-freqmhz = <0x69f6bcb>;
                        xlnx,pcw-nor-grp-a25-enable = <0x0>;
                        xlnx,trace-buffer-fifo-size = <0x80>;
                        xlnx,pcw-uiparam-ddr-dq-1-propogation-delay = <0xa0>;
                        xlnx,pcw-trace-grp-4bit-enable = <0x0>;
                        xlnx,pcw-qspi-peripheral-enable = <0x1>;
                        xlnx,pcw-dual-stack-qspi-data-mode = "<Select>";
                        xlnx,pcw-package-ddr-board-delay0 = <0x3e800>;
                        xlnx,s-axi-hp1-data-width = <0x40>;
                        xlnx,pcw-wdt-peripheral-divisor0 = <0x1>;
                        xlnx,pcw-package-ddr-board-delay1 = <0x35b60>;
                        xlnx,pcw-package-ddr-board-delay2 = <0x2bf20>;
                        xlnx,pcw-uart0-baud-rate = <0x1c200>;
                        xlnx,pcw-en-wdt = <0x0>;
                        xlnx,pcw-include-trace-buffer = <0x0>;
                        xlnx,pcw-m-axi-gp0-id-width = <0xc>;
                        xlnx,pcw-mio-16-direction = "inout";
                        xlnx,pcw-package-ddr-board-delay3 = <0x2ea18>;
                        xlnx,pcw-dci-peripheral-clksrc = "DDR , PLL";
                        xlnx,pcw-i2c1-grp-int-enable = <0x0>;
                        xlnx,pcw-p2f-uart1-intr = <0x0>;
                        xlnx,pcw-mio-31-iotype = "LVCMOS , 3.3V";
                        xlnx,pcw-usb1-peripheral-enable = <0x0>;
                        xlnx,pcw-act-can0-peripheral-freqmhz = <0x16b4ddc>;
                        xlnx,pcw-mio-3-direction = "inout";
                        xlnx,pcw-s-axi-hp3-freqmhz = <0xa>;
                        xlnx,pcw-m-axi-gp0-support-narrow-burst = <0x0>;
                        xlnx,pcw-nor-sram-cs0-t-tr = <0x1>;
                        xlnx,pcw-usb1-reset-enable = <0x0>;
                        xlnx,pcw-can1-can1-io = "<Select>";
                        xlnx,pcw-mio-17-pullup = "enabled";
                        xlnx,pcw-uiparam-ddr-clock-3-length-mm = <0x27>;
                        xlnx,pcw-sd1-peripheral-enable = <0x0>;
                        xlnx,s-axi-hp2-data-width = <0x40>;
                        xlnx,pcw-en-trace = <0x0>;
                        xlnx,pcw-enet1-baseaddr = <0xe000c000>;
                        xlnx,pcw-mio-26-direction = "inout";
                        xlnx,pcw-nor-sram-cs0-t-wc = <0xb>;
                        xlnx,pcw-spi0-grp-ss1-enable = <0x0>;
                        xlnx,pcw-ttc0-clk1-peripheral-clksrc = "CPU_1X";
                        xlnx,pcw-mio-47-iotype = "LVCMOS , 3.3V";
                        xlnx,pcw-nand-grp-d8-io = "<Select>";
                        xlnx,pcw-nor-grp-cs1-io = "<Select>";
                        xlnx,pcw-en-clktrig1-port = <0x0>;
                        xlnx,pcw-i2c-reset-select = "<Select>";
                        xlnx,pcw-act-uart-peripheral-freqmhz = <0xa>;
                        xlnx,pcw-enet0-highaddr = <0xe000bfff>;
                        xlnx,pcw-nor-grp-cs1-enable = <0x0>;
                        xlnx,pcw-usb1-peripheral-freqmhz = <0x3c>;
                        xlnx,pcw-usb0-reset-enable = <0x0>;
                        xlnx,m-axi-gp1-thread-id-width = <0xc>;
                        xlnx,pcw-nor-sram-cs0-t-wp = <0x1>;
                        xlnx,pcw-mio-34-pullup = "enabled";
                        xlnx,pcw-act-qspi-peripheral-freqmhz = <0xc8>;
                        xlnx,pcw-sdio-peripheral-valid = <0x1>;
                        xlnx,pcw-en-emio-trace = <0x0>;
                        xlnx,pcw-uart0-grp-full-enable = <0x0>;
                        xlnx,s-axi-hp3-data-width = <0x40>;
                        xlnx,pcw-uiparam-ddr-dqs-1-length-mm = <0x8>;
                        xlnx,pcw-uiparam-ddr-clock-3-package-length = <0x34090b8>;
                        xlnx,pcw-mio-36-direction = "inout";
                        xlnx,pcw-qspi-qspi-io = "MIO , 1 , .. , 6";
                        xlnx,pcw-fclk0-peripheral-clksrc = "IO , PLL";
                        xlnx,pcw-nand-cycles-t-clr = <0x1>;
                        xlnx,pcw-pll-bypassmode-enable = <0x0>;
                        xlnx,s-axi-acp-aruser-val = <0x1f>;
                        xlnx,pcw-io-io-pll-freqmhz = <0x640>;
                        xlnx,pcw-mio-22-iotype = "LVCMOS , 3.3V";
                        xlnx,pcw-mio-51-pullup = "enabled";
                        xlnx,pcw-p2f-sdio1-intr = <0x0>;
                        xlnx,pcw-qspi-grp-fbclk-io = "<Select>";
                        xlnx,use-s-axi-gp0 = <0x0>;
                        xlnx,use-s-axi-gp1 = <0x0>;
                        xlnx,pcw-i2c0-peripheral-enable = <0x1>;
                        xlnx,pcw-uiparam-ddr-dq-2-length-mm = <0x0>;
                        xlnx,pcw-nor-grp-sram-cs0-io = "<Select>";
                        xlnx,pcw-enet1-grp-mdio-io = "<Select>";
                        xlnx,pcw-enet0-peripheral-enable = <0x0>;
                        xlnx,pcw-p2f-usb0-intr = <0x0>;
                        xlnx,pcw-enet1-reset-io = "<Select>";
                        xlnx,pcw-mio-46-direction = "inout";
                        xlnx,pcw-spi1-grp-ss2-enable = <0x0>;
                        xlnx,pcw-nor-grp-a25-io = "<Select>";
                        xlnx,s-axi-hp2-id-width = <0x6>;
                        xlnx,pcw-en-emio-can0 = <0x0>;
                        xlnx,pcw-core1-fiq-intr = <0x0>;
                        xlnx,pcw-en-emio-can1 = <0x0>;
                        xlnx,pcw-mio-2-iotype = "LVCMOS , 3.3V";
                        xlnx,pcw-use-dma0 = <0x0>;
                        xlnx,pcw-can1-grp-clk-enable = <0x0>;
                        xlnx,pcw-mio-38-iotype = "LVCMOS , 3.3V";
                        xlnx,pcw-use-dma1 = <0x0>;
                        xlnx,pcw-use-dma2 = <0x0>;
                        xlnx,pcw-use-dma3 = <0x0>;
                        xlnx,pcw-usb-reset-select = "<Select>";
                        xlnx,pcw-mio-7-slew = "slow";
                        xlnx,pcw-ttc1-peripheral-enable = <0x0>;
                        xlnx,use-axi-nonsecure = <0x0>;
                        xlnx,pcw-sd0-grp-pow-enable = <0x0>;
                        xlnx,pcw-mio-4-slew = "slow";
                        xlnx,pcw-mio-25-pullup = "enabled";
                        xlnx,pcw-uiparam-ddr-dqs-0-propogation-delay = <0xa0>;
                        xlnx,pcw-mio-1-slew = "slow";
                        xlnx,pcw-trace-grp-32bit-io = "<Select>";
                        xlnx,pcw-act-ttc1-clk2-peripheral-freqmhz = <0x69f6bcb>;
                        xlnx,pcw-spi-peripheral-valid = <0x0>;
                        xlnx,pcw-mio-15-direction = "inout";
                        xlnx,pcw-en-ptp-enet0 = <0x0>;
                        xlnx,pcw-act-enet1-peripheral-freqmhz = <0xa>;
                        xlnx,pcw-mio-13-iotype = "LVCMOS , 3.3V";
                        xlnx,pcw-en-ptp-enet1 = <0x0>;
                        xlnx,pcw-mio-5-pullup = "disabled";
                        xlnx,pcw-en-clk3-port = <0x0>;
                        xlnx,pcw-mio-42-pullup = "enabled";
                        xlnx,pcw-sd1-grp-wp-io = "<Select>";
                        xlnx,pcw-fpga-fclk3-enable = <0x0>;
                        xlnx,pcw-mio-2-direction = "inout";
                        xlnx,pcw-p2f-dmac6-intr = <0x0>;
                        xlnx,pcw-en-clk0-port = <0x1>;
                        xlnx,pcw-s-axi-gp1-id-width = <0x6>;
                        xlnx,pcw-p2f-dmac3-intr = <0x0>;
                        xlnx,s-axi-acp-awuser-val = <0x1f>;
                        xlnx,pcw-uart1-baseaddr = <0xe0001000>;
                        xlnx,pcw-uiparam-ddr-clock-2-length-mm = <0x27>;
                        xlnx,pcw-p2f-dmac0-intr = <0x0>;
                        xlnx,pcw-uiparam-ddr-bank-addr-count = <0x3>;
                        xlnx,edk-iptype = "PERIPHERAL";
                        xlnx,pcw-en-emio-gpio = <0x0>;
                        xlnx,pcw-act-apu-peripheral-freqmhz = <0x27bc86bf>;
                        xlnx,pcw-trace-internal-width = <0x2>;
                        xlnx,pcw-mio-25-direction = "inout";
                        xlnx,pcw-act-fpga2-peripheral-freqmhz = <0xa>;
                        xlnx,pcw-uiparam-ddr-row-addr-count = <0xf>;
                        xlnx,pcw-trace-grp-32bit-enable = <0x0>;
                        xlnx,pcw-nor-cs0-t-pc = <0x1>;
                        xlnx,en-emio-enet0 = <0x0>;
                        xlnx,pcw-mio-29-iotype = "LVCMOS , 3.3V";
                        xlnx,pcw-mio-30-iotype = "LVCMOS , 3.3V";
                        xlnx,pcw-uart0-highaddr = <0xe0000fff>;
                        xlnx,en-emio-enet1 = <0x0>;
                        xlnx,pcw-nor-cs0-we-time = <0x0>;
                        xlnx,use-s-axi-hp0 = <0x1>;
                        xlnx,use-s-axi-hp1 = <0x0>;
                        xlnx,use-s-axi-hp2 = <0x0>;
                        xlnx,use-s-axi-hp3 = <0x0>;
                        xlnx,pcw-enet1-peripheral-clksrc = "IO , PLL";
                        xlnx,pcw-s-axi-hp1-id-width = <0x6>;
                        xlnx,pcw-uiparam-ddr-dq-3-package-length = <0x4d8d458>;
                        xlnx,pcw-mio-16-pullup = "enabled";
                        xlnx,pcw-trace-trace-io = "<Select>";
                        xlnx,pcw-use-trace = <0x0>;
                        xlnx,pcw-cpu-cpu-6x4x-max-range = <0x29b>;
                        xlnx,pcw-sdio1-baseaddr = <0xe0101000>;
                        xlnx,pcw-p2f-enet1-intr = <0x0>;
                        xlnx,pcw-nor-cs0-t-rc = <0xb>;
                        xlnx,pcw-single-qspi-data-mode = "x4";
                        xlnx,pcw-uiparam-ddr-dqs-0-length-mm = <0x10e14a0>;
                        xlnx,pcw-uiparam-ddr-dqs-0-package-length = <0x608c8d8>;
                        xlnx,pcw-mio-35-direction = "inout";
                        xlnx,pcw-gpio-mio-gpio-enable = <0x1>;
                        xlnx,pcw-spi0-grp-ss0-enable = <0x0>;
                        xlnx,fclk-clk0-buf;
                        xlnx,pcw-mio-9-iotype = "LVCMOS , 3.3V";
                        xlnx,pcw-m-axi-gp0-enable-static-remap = <0x0>;
                        xlnx,pcw-mio-46-iotype = "LVCMOS , 3.3V";
                        xlnx,pcw-nand-cycles-t-rea = <0x1>;
                        xlnx,pcw-sdio0-highaddr = <0xe0100fff>;
                        xlnx,pcw-act-usb1-peripheral-freqmhz = <0x3c>;
                        compatible = "xlnx,processing-system7-5.5";
                        xlnx,pcw-fclk3-peripheral-clksrc = "IO , PLL";
                        xlnx,pcw-preset-bank0-voltage = "LVCMOS , 3.3V";
                        xlnx,pcw-nor-grp-cs0-enable = <0x0>;
                        xlnx,pcw-mio-33-pullup = "enabled";
                        xlnx,pcw-trace-pipeline-width = <0x8>;
                        xlnx,pcw-ftm-cti-in0 = "DISABLED";
                        xlnx,pcw-ftm-cti-in1 = "DISABLED";
                        xlnx,pcw-ftm-cti-in2 = "DISABLED";
                        xlnx,pcw-ftm-cti-in3 = "DISABLED";
                        xlnx,pcw-uiparam-ddr-dq-1-length-mm = <0xb>;
                        xlnx,pcw-mio-45-direction = "inout";
                        xlnx,pcw-uart-peripheral-divisor0 = <0x1>;
                        xlnx,use-m-axi-gp0 = <0x1>;
                        xlnx,pcw-mio-primitive = <0x36>;
                        xlnx,use-m-axi-gp1 = <0x0>;
                        xlnx,pcw-ddr-priority-readport-0 = "<Select>";
                        xlnx,pcw-ddr-priority-readport-1 = "<Select>";
                        xlnx,pcw-en-pjtag = <0x0>;
                        xlnx,pcw-ddr-priority-readport-2 = "<Select>";
                        xlnx,pcw-fclk0-peripheral-divisor0 = <0x8>;
                        xlnx,pcw-nor-cs0-t-tr = <0x1>;
                        xlnx,pcw-ddr-priority-readport-3 = "<Select>";
                        xlnx,pcw-fclk0-peripheral-divisor1 = <0x4>;
                        xlnx,pcw-gpio-emio-gpio-io = "<Select>";
                        xlnx,pcw-smc-peripheral-valid = <0x0>;
                        xlnx,pcw-uart1-peripheral-enable = <0x0>;
                        xlnx,pcw-act-smc-peripheral-freqmhz = <0xa>;
                        xlnx,pcw-m-axi-gp1-enable-static-remap = <0x0>;
                        xlnx,pcw-mio-21-iotype = "LVCMOS , 3.3V";
                        xlnx,pcw-mio-49-pullup = "enabled";
                        xlnx,pcw-mio-50-pullup = "enabled";
                        xlnx,pcw-p2f-cti-intr = <0x0>;
                        xlnx,pcw-mio-tree-signals = "gpio[0]#qspi0_ss_b#qspi0_io[0]#qspi0_io[1]#qspi0_io[2]#qspi0_io[3]/HOLD_B#qspi0_sclk#gpio[7]#gpio[8]#gpio[9]#gpio[10]#gpio[11]#gpio[12]#gpio[13]#gpio[14]#gpio[15]#gpio[16]#gpio[17]#gpio[18]#gpio[19]#gpio[20]#gpio[21]#gpio[22]#gpio[23]#gpio[24]#gpio[25]#gpio[26]#gpio[27]#gpio[28]#gpio[29]#gpio[30]#gpio[31]#gpio[32]#gpio[33]#gpio[34]#gpio[35]#gpio[36]#gpio[37]#gpio[38]#gpio[39]#clk#cmd#data[0]#data[1]#data[2]#data[3]#gpio[46]#gpio[47]#gpio[48]#gpio[49]#scl#sda#scl#sda";
                        xlnx,pcw-nor-cs0-t-wc = <0xb>;
                        xlnx,pcw-p2f-smc-intr = <0x0>;
                        xlnx,pcw-qspi-grp-ss1-enable = <0x0>;
                        xlnx,pcw-s-axi-hp2-freqmhz = <0xa>;
                        xlnx,pcw-spi0-grp-ss2-io = "<Select>";
                        xlnx,pcw-can1-baseaddr = <0xe0009000>;
                        xlnx,pcw-uiparam-ddr-col-addr-count = <0xa>;
                        xlnx,pcw-ddr-lpr-to-critical-priority-level = <0x2>;
                        xlnx,pcw-armpll-ctrl-fbdiv = <0x28>;
                        xlnx,pcw-spi1-grp-ss1-enable = <0x0>;
                        xlnx,pcw-en-emio-pjtag = <0x0>;
                        xlnx,pcw-uiparam-ddr-high-temp = "Normal , (0-85)";
                        xlnx,pcw-uiparam-ddr-dqs-3-propogation-delay = <0xa0>;
                        xlnx,pcw-nor-cs0-t-wp = <0x1>;
                        xlnx,pcw-trace-grp-2bit-enable = <0x0>;
                        xlnx,pcw-ttc0-clk2-peripheral-freqmhz = <0x7f28155>;
                        xlnx,pcw-can0-highaddr = <0xe0008fff>;
                        xlnx,pcw-mio-1-iotype = "LVCMOS , 3.3V";
                        xlnx,pcw-mio-37-iotype = "LVCMOS , 3.3V";
                        xlnx,pcw-use-cross-trigger = <0x0>;
                        xlnx,pcw-mio-14-direction = "inout";
                        xlnx,pcw-s-axi-acp-freqmhz = <0xa>;
                        xlnx,pcw-fclk1-peripheral-divisor0 = <0xa>;
                        xlnx,pcw-fclk1-peripheral-divisor1 = <0x5>;
                        xlnx,pcw-ttc0-ttc0-io = "<Select>";
                        xlnx,pcw-spi1-grp-ss2-io = "<Select>";
                        xlnx,pcw-ttc1-clk2-peripheral-clksrc = "CPU_1X";
                        xlnx,pcw-sd0-grp-wp-io = "<Select>";
                        xlnx,pcw-i2c-reset-polarity = "Active , Low";
                        xlnx,pcw-mio-24-pullup = "enabled";
                        xlnx,pcw-ddr-hprlpr-queue-partition = "HPR(0)/LPR(32)";
                        xlnx,pcw-apu-peripheral-freqmhz = <0x27bc86aa>;
                        xlnx,pcw-mio-1-direction = "out";
                        xlnx,pcw-tpiu-peripheral-clksrc = "External";
                        xlnx,pcw-usb1-highaddr = <0xe0103fff>;
                        xlnx,pcw-core0-irq-intr = <0x0>;
                        xlnx,s-axi-acp-id-width = <0x3>;
                        xlnx,pcw-uiparam-ddr-memory-type = "DDR , 3 , (Low , Voltage)";
                        xlnx,pcw-uiparam-ddr-clock-1-length-mm = <0x27>;
                        xlnx,pcw-mio-24-direction = "inout";
                        xlnx,pcw-gpio-emio-gpio-width = <0x40>;
                        xlnx,pcw-gpio-highaddr = <0xe000afff>;
                        xlnx,pcw-uiparam-ddr-clock-1-propogation-delay = <0xa0>;
                        xlnx,pcw-i2c0-baseaddr = <0xe0004000>;
                        xlnx,irq-f2p-mode = "DIRECT";
                        xlnx,pcw-mio-12-iotype = "LVCMOS , 3.3V";
                        xlnx,pcw-mio-4-pullup = "disabled";
                        xlnx,pcw-mio-41-pullup = "enabled";
                        xlnx,pcw-clk3-freq = <0x989680>;
                        xlnx,pcw-can1-peripheral-enable = <0x0>;
                        xlnx,pcw-fclk2-peripheral-divisor0 = <0x1>;
                        xlnx,pcw-mio-51-slew = "slow";
                        xlnx,pcw-fclk2-peripheral-divisor1 = <0x1>;
                        xlnx,pcw-fpga-fclk2-enable = <0x0>;
                        xlnx,pcw-clk0-freq = <0x2faf080>;
                        xlnx,pcw-mio-47-slew = "slow";
                        xlnx,pcw-sdio-peripheral-divisor0 = <0x10>;
                        xlnx,pcw-use-expanded-iop = <0x0>;
                        xlnx,pcw-mio-44-slew = "slow";
                        xlnx,pcw-qspi-peripheral-divisor0 = <0x8>;
                        xlnx,pcw-gp0-num-read-threads = <0x4>;
                        xlnx,pcw-en-rst3-port = <0x0>;
                        xlnx,pcw-mio-34-direction = "inout";
                        xlnx,pcw-mio-41-slew = "slow";
                        xlnx,pcw-tpiu-peripheral-divisor0 = <0x1>;
                        xlnx,pcw-en-rst0-port = <0x1>;
                        xlnx,pcw-mio-28-iotype = "LVCMOS , 3.3V";
                        xlnx,pcw-mio-37-slew = "slow";
                        xlnx,pcw-sd1-grp-pow-enable = <0x0>;
                        xlnx,pcw-ttc0-baseaddr = <0xe0104000>;
                        xlnx,pcw-mio-34-slew = "slow";
                        xlnx,pcw-en-emio-sram-int = <0x0>;
                        xlnx,pcw-uiparam-ddr-dqs-to-clk-delay-0 = <0x0>;
                        xlnx,pcw-uiparam-ddr-dqs-to-clk-delay-1 = <0x0>;
                        xlnx,pcw-uiparam-ddr-dqs-to-clk-delay-2 = <0x0>;
                        xlnx,pcw-uiparam-ddr-dqs-to-clk-delay-3 = <0x0>;
                        xlnx,pcw-mio-31-slew = "slow";
                        xlnx,pcw-sd1-grp-wp-enable = <0x0>;
                        xlnx,pcw-mio-15-pullup = "enabled";
                        xlnx,pcw-fclk3-peripheral-divisor0 = <0x1>;
                        xlnx,pcw-fclk3-peripheral-divisor1 = <0x1>;
                        xlnx,pcw-uiparam-ddr-dq-0-length-mm = <0x11>;
                        xlnx,pcw-mio-27-slew = "slow";
                        xlnx,pcw-smc-peripheral-freqmhz = <0x64>;
                        xlnx,pcw-num-f2p-intr-inputs = <0x1>;
                        xlnx,pcw-wdt-wdt-io = "<Select>";
                        xlnx,pcw-uiparam-ddr-dq-0-propogation-delay = <0xa0>;
                        xlnx,pcw-mio-24-slew = "slow";
                        xlnx,pcw-mio-44-direction = "inout";
                        xlnx,pcw-fpga0-peripheral-freqmhz = <0x32>;
                        xlnx,pcw-mio-8-iotype = "LVCMOS , 3.3V";
                        xlnx,pcw-iopll-ctrl-fbdiv = <0x30>;
                        xlnx,pcw-mio-45-iotype = "LVCMOS , 3.3V";
                        xlnx,pcw-p2f-can1-intr = <0x0>;
                        xlnx,pcw-ddr-priority-writeport-0 = "<Select>";
                        xlnx,pcw-i2c0-reset-io = "<Select>";
                        xlnx,pcw-ddr-priority-writeport-1 = "<Select>";
                        xlnx,pcw-ddr-priority-writeport-2 = "<Select>";
                        xlnx,pcw-mio-21-slew = "slow";
                        xlnx,pcw-ddr-priority-writeport-3 = "<Select>";
                        xlnx,pcw-en-can0 = <0x0>;
                        xlnx,pcw-mio-17-slew = "slow";
                        xlnx,pcw-en-can1 = <0x0>;
                        xlnx,pcw-fpga3-peripheral-freqmhz = <0x32>;
                        xlnx,pcw-trace-grp-16bit-io = "<Select>";
                        xlnx,pcw-cpu-peripheral-divisor0 = <0x2>;
                        xlnx,pcw-m-axi-gp1-support-narrow-burst = <0x0>;
                        xlnx,pcw-mio-32-pullup = "enabled";
                        xlnx,pcw-usb0-peripheral-enable = <0x0>;
                        xlnx,pcw-mio-14-slew = "slow";
                        xlnx,pcw-spi0-baseaddr = <0xe0006000>;
                        xlnx,pcw-uiparam-ddr-train-read-gate = <0x1>;
                        xlnx,gp1-en-modifiable-txn = <0x1>;
                        xlnx,name = "processing_system7_0";
                        xlnx,pcw-act-spi-peripheral-freqmhz = <0xa>;
                        xlnx,pcw-mio-11-slew = "slow";
                        xlnx,pcw-ttc1-clk1-peripheral-freqmhz = <0x7f28155>;
                        xlnx,pcw-en-emio-modem-uart0 = <0x0>;
                        xlnx,pcw-dq-width = <0x20>;
                        xlnx,pcw-en-emio-modem-uart1 = <0x0>;
                        xlnx,pcw-sd0-peripheral-enable = <0x1>;
                        xlnx,pcw-nor-grp-cs0-io = "<Select>";
                        xlnx,pcw-can-peripheral-valid = <0x0>;
                        xlnx,pcw-m-axi-gp1-id-width = <0xc>;
                        xlnx,pcw-ttc0-clk0-peripheral-clksrc = "CPU_1X";
                        xlnx,pcw-act-ttc0-clk1-peripheral-freqmhz = <0x69f6bcb>;
                        xlnx,pcw-mio-19-iotype = "LVCMOS , 3.3V";
                        xlnx,pcw-mio-20-iotype = "LVCMOS , 3.3V";
                        xlnx,pcw-wdt-peripheral-enable = <0x0>;
                        xlnx,pcw-mio-13-direction = "inout";
                        xlnx,pcw-enet1-grp-mdio-enable = <0x0>;
                        xlnx,pcw-mio-48-pullup = "enabled";
                        xlnx,pcw-sdio-peripheral-clksrc = "IO , PLL";
                        xlnx,pcw-p2f-dmac-abort-intr = <0x0>;
                        xlnx,pcw-nor-peripheral-enable = <0x0>;
                        xlnx,pcw-en-sdio0 = <0x1>;
                        xlnx,pcw-en-sdio1 = <0x0>;
                        xlnx,pcw-ddr-peripheral-divisor0 = <0x2>;
                        xlnx,pcw-mio-0-direction = "inout";
                        xlnx,pcw-uiparam-ddr-dqs-1-package-length = <0x4bd1ca4>;
                        xlnx,pcw-uiparam-ddr-enable = <0x1>;
                        xlnx,pcw-spi1-grp-ss0-enable = <0x0>;
                        xlnx,pcw-usb-reset-polarity = "Active , Low";
                        xlnx,pcw-fclk-clk2-buf;
                        xlnx,pcw-p2f-uart0-intr = <0x0>;
                        xlnx,pcw-uiparam-ddr-t-rcd = <0x7>;
                        xlnx,ps7-si-rev = "PRODUCTION";
                        xlnx,pcw-mio-0-iotype = "LVCMOS , 3.3V";
                        xlnx,pcw-uiparam-ddr-clock-0-length-mm = <0x27>;
                        xlnx,pcw-ddr-ram-baseaddr = <0x100000>;
                        xlnx,pcw-mio-36-iotype = "LVCMOS , 3.3V";
                        xlnx,pcw-act-can1-peripheral-freqmhz = <0x16b4ddc>;
                        xlnx,pcw-cpu-cpu-pll-freqmhz = <0x4f790c08>;
                        xlnx,pcw-mio-23-direction = "inout";
                        xlnx,pcw-uiparam-ddr-train-write-level = <0x1>;
                        xlnx,pcw-ddr-write-to-critical-priority-level = <0x2>;
                        xlnx,pcw-nand-peripheral-enable = <0x0>;
                        xlnx,pcw-en-gpio = <0x1>;
                        xlnx,pcw-spi0-spi0-io = "<Select>";
                        xlnx,pcw-enet1-highaddr = <0xe000cfff>;
                        xlnx,pcw-use-high-ocm = <0x0>;
                        xlnx,pcw-en-emio-sdio0 = <0x0>;
                        xlnx,pcw-mio-23-pullup = "enabled";
                        xlnx,pcw-en-emio-sdio1 = <0x0>;
                        xlnx,pcw-gp1-en-modifiable-txn = <0x1>;
                        xlnx,pcw-mio-9-direction = "inout";
                        xlnx,pcw-uart-peripheral-clksrc = "IO , PLL";
                        xlnx,pcw-en-clktrig3-port = <0x0>;
                        xlnx,pcw-qspi-peripheral-clksrc = "IO , PLL";
                        xlnx,pcw-uiparam-ddr-board-delay0 = <0x3d090>;
                        xlnx,pcw-uiparam-ddr-board-delay1 = <0x3d090>;
                        xlnx,pcw-uiparam-ddr-board-delay2 = <0x3d090>;
                        xlnx,pcw-mio-53-iotype = "LVCMOS , 3.3V";
                        xlnx,pcw-uiparam-ddr-board-delay3 = <0x3d090>;
                        xlnx,pcw-en-clktrig0-port = <0x0>;
                        xlnx,pcw-dm-width = <0x4>;
                        xlnx,pcw-i2c0-i2c0-io = "MIO , 50 , .. , 51";
                        xlnx,pcw-mio-33-direction = "inout";
                        xlnx,pcw-mio-11-iotype = "LVCMOS , 3.3V";
                        xlnx,pcw-mio-3-pullup = "disabled";
                        xlnx,fclk-clk3-buf;
                        xlnx,pcw-mio-39-pullup = "enabled";
                        xlnx,pcw-mio-40-pullup = "enabled";
                        xlnx,pcw-uart0-grp-full-io = "<Select>";
                        xlnx,pcw-fpga-fclk1-enable = <0x1>;
                        xlnx,pcw-ttc0-peripheral-enable = <0x0>;
                        xlnx,pcw-uiparam-ddr-t-rc = <0x2e7ddb0>;
                        xlnx,pcw-uiparam-ddr-adv-enable = <0x0>;
                        xlnx,pcw-i2c-reset-enable = <0x0>;
                        xlnx,pcw-s-axi-hp1-freqmhz = <0x32>;
                        xlnx,use-default-acp-user-val = <0x0>;
                        xlnx,pcw-act-i2c-peripheral-freqmhz = <0x32>;
                        xlnx,pcw-uiparam-ddr-t-faw = <0x28>;
                        xlnx,preset = "None";
                        xlnx,pcw-use-proc-event-bus = <0x0>;
                        xlnx,pcw-uiparam-ddr-t-rp = <0x7>;
                        xlnx,pcw-p2f-sdio0-intr = <0x0>;
                        xlnx,pcw-mio-43-direction = "inout";
                        xlnx,s-axi-hp3-id-width = <0x6>;
                        xlnx,pcw-mio-27-iotype = "LVCMOS , 3.3V";
                        xlnx,pcw-uiparam-ddr-dq-3-propogation-delay = <0xa0>;
                        xlnx,pcw-p2f-spi1-intr = <0x0>;
                        xlnx,pcw-spi-peripheral-freqmhz = <0x9ef21aa>;
                        xlnx,m-axi-gp0-thread-id-width = <0xc>;
                        xlnx,s-axi-gp0-id-width = <0x6>;
                        xlnx,pcw-mio-14-pullup = "enabled";
                        xlnx,pcw-mio-9-slew = "slow";
                        xlnx,m-axi-gp0-enable-static-remap = <0x0>;
                        xlnx,pcw-mio-53-direction = "inout";
                        xlnx,pcw-mio-6-slew = "slow";
                        xlnx,pcw-mio-7-iotype = "LVCMOS , 3.3V";
                        xlnx,pcw-mio-44-iotype = "LVCMOS , 3.3V";
                        xlnx,pcw-use-fabric-interrupt = <0x0>;
                        xlnx,pcw-act-ttc1-clk0-peripheral-freqmhz = <0x69f6bcb>;
                        xlnx,pcw-mio-3-slew = "slow";
                        xlnx,baseaddr = <0x0>;
                        xlnx,pcw-sd1-grp-cd-io = "<Select>";
                        xlnx,pcw-use-s-axi-gp0 = <0x0>;
                        xlnx,pcw-use-s-axi-gp1 = <0x0>;
                        xlnx,pcw-en-usb0 = <0x0>;
                        xlnx,pcw-mio-0-slew = "slow";
                        xlnx,pcw-nor-grp-sram-int-io = "<Select>";
                        xlnx,pcw-en-usb1 = <0x0>;
                        xlnx,pcw-mio-12-direction = "inout";
                        xlnx,pcw-pjtag-peripheral-enable = <0x0>;
                        xlnx,pcw-pcap-peripheral-clksrc = "IO , PLL";
                        xlnx,pcw-m-axi-gp1-thread-id-width = <0xc>;
                        xlnx,pcw-mio-31-pullup = "enabled";
                        xlnx,pcw-usb-reset-enable = <0x0>;
                        xlnx,pcw-mio-tree-peripherals = "GPIO#Quad , SPI , Flash#Quad , SPI , Flash#Quad , SPI , Flash#Quad , SPI , Flash#Quad , SPI , Flash#Quad , SPI , Flash#GPIO#GPIO#GPIO#GPIO#GPIO#GPIO#GPIO#GPIO#GPIO#GPIO#GPIO#GPIO#GPIO#GPIO#GPIO#GPIO#GPIO#GPIO#GPIO#GPIO#GPIO#GPIO#GPIO#GPIO#GPIO#GPIO#GPIO#GPIO#GPIO#GPIO#GPIO#GPIO#GPIO#SD , 0#SD , 0#SD , 0#SD , 0#SD , 0#SD , 0#GPIO#GPIO#GPIO#GPIO#I2C , 0#I2C , 0#I2C , 1#I2C , 1";
                        xlnx,s-axi-hp0-id-width = <0x6>;
                        xlnx,include-trace-buffer = <0x0>;
                        xlnx,pcw-use-cr-fabric = <0x1>;
                        xlnx,pcw-enet0-peripheral-clksrc = "IO , PLL";
                        xlnx,package-name = "clg400";
                        xlnx,m-axi-gp1-enable-static-remap = <0x0>;
                        xlnx,pcw-en-clk2-port = <0x0>;
                        xlnx,pcw-p2f-dmac5-intr = <0x0>;
                        xlnx,pcw-mio-18-iotype = "LVCMOS , 3.3V";
                        xlnx,pcw-mio-22-direction = "inout";
                        xlnx,pcw-mio-47-pullup = "enabled";
                        xlnx,pcw-uart1-highaddr = <0xe0001fff>;
                        xlnx,pcw-apu-clk-ratio-enable = "6:2:1";
                        xlnx,pcw-act-fpga0-peripheral-freqmhz = <0x32>;
                        xlnx,pcw-p2f-dmac2-intr = <0x0>;
                        xlnx,pcw-fclk2-peripheral-clksrc = "IO , PLL";
                        xlnx,rable = <0x1>;
                        xlnx,pcw-usb1-usb1-io = "<Select>";
                        xlnx,ip-name = "processing_system7";
                        xlnx,pcw-mio-8-direction = "out";
                        xlnx,pcw-s-axi-hp2-id-width = <0x6>;
                        xlnx,pcw-act-fpga3-peripheral-freqmhz = <0xa>;
                        xlnx,pcw-qspi-grp-fbclk-enable = <0x0>;
                        xlnx,pcw-qspi-grp-io1-io = "<Select>";
                        xlnx,pcw-trace-buffer-fifo-size = <0x80>;
                        xlnx,pcw-use-trace-data-edge-detector = <0x0>;
                        xlnx,pcw-mio-35-iotype = "LVCMOS , 3.3V";
                        xlnx,pcw-sd1-sd1-io = "<Select>";
                        xlnx,pcw-en-enet0 = <0x0>;
                        xlnx,pcw-en-enet1 = <0x0>;
                        xlnx,pcw-mio-32-direction = "inout";
                        xlnx,pcw-sd0-grp-wp-enable = <0x0>;
                        xlnx,include-acp-trans-check = <0x0>;
                        xlnx,pcw-sdio1-highaddr = <0xe0101fff>;
                        xlnx,pcw-i2c-peripheral-freqmhz = <0x69f6bcb>;
                        xlnx,pcw-uart0-peripheral-enable = <0x0>;
                        xlnx,pcw-p2f-enet0-intr = <0x0>;
                        xlnx,pcw-spi0-grp-ss1-io = "<Select>";
                        xlnx,pcw-mio-22-pullup = "enabled";
                        xlnx,pcw-can0-can0-io = "<Select>";
                        xlnx,pcw-s-axi-gp1-freqmhz = <0xa>;
                        xlnx,pcw-en-ddr = <0x1>;
                        xlnx,pcw-qspi-internal-highaddress = <0xfcffffff>;
                        xlnx,pcw-mio-52-iotype = "LVCMOS , 3.3V";
                        xlnx,pcw-en-emio-enet0 = <0x0>;
                        xlnx,pcw-uiparam-ddr-clock-0-package-length = <0x34090b8>;
                        xlnx,pcw-en-emio-enet1 = <0x0>;
                        xlnx,pcw-uiparam-ddr-dqs-2-propogation-delay = <0xa0>;
                        xlnx,pcw-mio-42-direction = "inout";
                        xlnx,pcw-use-s-axi-hp0 = <0x1>;
                        xlnx,pcw-use-s-axi-hp1 = <0x0>;
                        xlnx,pcw-enet0-peripheral-divisor0 = <0x1>;
                        xlnx,pcw-mio-10-iotype = "LVCMOS , 3.3V";
                        xlnx,pcw-use-s-axi-hp2 = <0x0>;
                        xlnx,pcw-enet0-peripheral-divisor1 = <0x1>;
                        xlnx,pcw-mio-2-pullup = "disabled";
                        xlnx,pcw-use-s-axi-hp3 = <0x0>;
                        xlnx,pcw-mio-38-pullup = "enabled";
                        xlnx,pcw-spi1-grp-ss1-io = "<Select>";
                        xlnx,pcw-fpga-fclk0-enable = <0x1>;
                        xlnx,pcw-uiparam-ddr-dqs-2-package-length = <0x39bb4c0>;
                        xlnx,pcw-p2f-qspi-intr = <0x0>;
                        xlnx,pcw-ttc1-clk1-peripheral-clksrc = "CPU_1X";
                        xlnx,pcw-gp1-num-write-threads = <0x4>;
                        xlnx,pcw-fclk-clk0-buf;
                        xlnx,pcw-uiparam-ddr-use-internal-vref = <0x0>;
                        xlnx,trace-buffer-clock-delay = <0xc>;
                        xlnx,pcw-en-4k-timer = <0x0>;
                        xlnx,pcw-p2f-i2c1-intr = <0x0>;
                        xlnx,pcw-mio-52-direction = "inout";
                        xlnx,pcw-override-basic-clock = <0x0>;
                        xlnx,pcw-mio-26-iotype = "LVCMOS , 3.3V";
                        xlnx,pcw-can1-highaddr = <0xe0009fff>;
                        xlnx,dq-width = <0x20>;
                        xlnx,pcw-s-axi-hp0-data-width = <0x40>;
                        xlnx,pcw-en-emio-i2c0 = <0x0>;
                        xlnx,pcw-ttc0-clk0-peripheral-freqmhz = <0x7f28155>;
                        xlnx,use-s-axi-acp = <0x0>;
                        xlnx,pcw-en-emio-i2c1 = <0x0>;
                        xlnx,pcw-sd0-grp-cd-io = "<Select>";
                        xlnx,pcw-uiparam-ddr-clock-0-propogation-delay = <0xa0>;
                        xlnx,pcw-pcap-peripheral-freqmhz = <0xc8>;
                        xlnx,pcw-act-dci-peripheral-freqmhz = <0x9b028a>;
                        xlnx,pcw-mio-11-direction = "inout";
                        xlnx,pcw-enet1-peripheral-divisor0 = <0x1>;
                        xlnx,pcw-use-default-acp-user-val = <0x0>;
                        xlnx,pcw-ddrpll-ctrl-fbdiv = <0x20>;
                        xlnx,pcw-enet1-peripheral-divisor1 = <0x1>;
                        xlnx,pcw-mio-13-pullup = "enabled";
                        xlnx,pcw-ps7-si-rev = "PRODUCTION";
                        xlnx,pcw-can0-peripheral-enable = <0x0>;
                        xlnx,pcw-use-m-axi-gp0 = <0x1>;
                        xlnx,pcw-en-emio-cd-sdio0 = <0x0>;
                        xlnx,pcw-uart0-uart0-io = "<Select>";
                        xlnx,pcw-use-m-axi-gp1 = <0x0>;
                        xlnx,pcw-en-emio-cd-sdio1 = <0x0>;
                        xlnx,pcw-core1-irq-intr = <0x0>;
                        xlnx,pcw-mio-6-iotype = "LVCMOS , 3.3V";
                        xlnx,pcw-mio-43-iotype = "LVCMOS , 3.3V";
                        xlnx,pcw-i2c1-reset-enable = <0x0>;
                        xlnx,pcw-s-axi-hp1-data-width = <0x40>;
                        xlnx,pcw-trace-grp-8bit-enable = <0x0>;
                        xlnx,dqs-width = <0x4>;
                        xlnx,pcw-i2c1-baseaddr = <0xe0005000>;
                        xlnx,fclk-clk1-buf;
                        xlnx,pcw-mio-21-direction = "inout";
                        xlnx,pcw-mio-29-pullup = "enabled";
                        xlnx,pcw-mio-30-pullup = "enabled";
                        xlnx,trace-internal-width = <0x2>;
                        xlnx,pcw-s-axi-hp0-freqmhz = <0x32>;
                        xlnx,pcw-usb0-baseaddr = <0xe0102000>;
                        xlnx,pcw-i2c0-highaddr = <0xe0004fff>;
                        xlnx,pcw-mio-7-direction = "out";
                        xlnx,pcw-i2c0-reset-enable = <0x0>;
                        xlnx,pcw-mio-53-slew = "slow";
                        xlnx,pcw-sdio-peripheral-freqmhz = <0x64>;
                        xlnx,pcw-uart1-uart1-io = "<Select>";
                        xlnx,pcw-dqs-width = <0x4>;
                        xlnx,pcw-s-axi-hp2-data-width = <0x40>;
                        xlnx,pcw-clk2-freq = <0x989680>;
                        xlnx,pcw-mio-49-slew = "slow";
                        xlnx,pcw-mio-50-slew = "slow";
                        xlnx,pcw-mio-17-iotype = "LVCMOS , 3.3V";
                        xlnx,pcw-en-emio-ttc0 = <0x0>;
                        xlnx,pcw-mio-9-pullup = "enabled";
                        xlnx,pcw-en-emio-ttc1 = <0x0>;
                        xlnx,pcw-mio-46-pullup = "enabled";
                        xlnx,pcw-mio-31-direction = "inout";
                        xlnx,pcw-mio-46-slew = "slow";
                        xlnx,pcw-sd1-grp-cd-enable = <0x0>;
                        xlnx,dm-width = <0x4>;
                        xlnx,pcw-ttc1-baseaddr = <0xe0105000>;
                        xlnx,pcw-i2c0-grp-int-io = "<Select>";
                        xlnx,pcw-mio-43-slew = "slow";
                        xlnx,pcw-use-axi-fabric-idle = <0x0>;
                        xlnx,pcw-en-rst2-port = <0x0>;
                        xlnx,pcw-gpio-emio-gpio-enable = <0x0>;
                        xlnx,pcw-mio-39-slew = "slow";
                        xlnx,pcw-mio-40-slew = "slow";
                        xlnx,gp0-en-modifiable-txn = <0x1>;
                        xlnx,pcw-uart1-grp-full-io = "<Select>";
                        xlnx,pcw-uart-peripheral-valid = <0x0>;
                        xlnx,pcw-mio-36-slew = "slow";
                        xlnx,pcw-ttc0-highaddr = <0xe0104fff>;
                        xlnx,pcw-uiparam-ddr-dq-0-package-length = <0x63b19b4>;
                        xlnx,pcw-s-axi-hp3-data-width = <0x40>;
                        xlnx,pcw-enet0-peripheral-freqmhz = "1000 , Mbps";
                        xlnx,trace-pipeline-width = <0x8>;
                        xlnx,m-axi-gp0-id-width = <0xc>;
                        xlnx,pcw-mio-33-slew = "slow";
                        xlnx,pcw-mio-34-iotype = "LVCMOS , 3.3V";
                        xlnx,pcw-use-coresight = <0x0>;
                        xlnx,pcw-uiparam-ddr-bus-width = "16 , Bit";
                        xlnx,pcw-en-emio-spi0 = <0x0>;
                        xlnx,pcw-en-emio-spi1 = <0x0>;
                        xlnx,pcw-i2c1-reset-io = "<Select>";
                        xlnx,pcw-mio-29-slew = "slow";
                        xlnx,pcw-mio-30-slew = "slow";
                        xlnx,pcw-mio-41-direction = "inout";
                        xlnx,pcw-use-debug = <0x0>;
                        xlnx,pcw-smc-peripheral-divisor0 = <0x1>;
                        xlnx,pcw-i2c1-grp-int-io = "<Select>";
                        xlnx,pcw-mio-26-slew = "slow";
                        xlnx,pcw-s-axi-acp-aruser-val = <0x1f>;
                        xlnx,pcw-uiparam-ddr-t-ras-min = <0x23>;
                        xlnx,pcw-can1-peripheral-clksrc = "External";
                        xlnx,pcw-irq-f2p-mode = "DIRECT";
                        xlnx,pcw-mio-21-pullup = "enabled";
                        xlnx,pcw-usb0-reset-io = "<Select>";
                        xlnx,pcw-mio-23-slew = "slow";
                        xlnx,pcw-uiparam-ddr-train-data-eye = <0x1>;
                        xlnx,pcw-spi1-baseaddr = <0xe0007000>;
                        xlnx,pcw-p2f-can0-intr = <0x0>;
                        xlnx,pcw-fpga1-peripheral-freqmhz = <0x20>;
                        xlnx,pcw-s-axi-acp-id-width = <0x3>;
                        xlnx,pcw-smc-peripheral-clksrc = "IO , PLL";
                        xlnx,pcw-mio-19-slew = "slow";
                        xlnx,pcw-mio-20-slew = "slow";
                        xlnx,pcw-nand-grp-d8-enable = <0x0>;
                        xlnx,pcw-nor-sram-cs1-t-pc = <0x1>;
                        xlnx,pcw-mio-51-iotype = "LVCMOS , 3.3V";
                        xlnx,pcw-enet-reset-select = "<Select>";
                        xlnx,pcw-mio-16-slew = "slow";
                        xlnx,pcw-dci-peripheral-freqmhz = <0x9b0398>;
                        xlnx,pcw-spi0-highaddr = <0xe0006fff>;
                        xlnx,pcw-mio-13-slew = "slow";
                        xlnx,pcw-mio-51-direction = "inout";
                        xlnx,pcw-mio-1-pullup = "enabled";
                        xlnx,pcw-mio-10-slew = "slow";
                        xlnx,pcw-mio-37-pullup = "enabled";
                        xlnx,pcw-nor-sram-cs1-t-rc = <0xb>;
                        xlnx,pcw-ttc1-clk2-peripheral-freqmhz = <0x7f28155>;
                        xlnx,pcw-mio-10-direction = "inout";
                        xlnx,pcw-uiparam-ddr-clock-3-propogation-delay = <0xa0>;
                        xlnx,pcw-use-ddr-bypass = <0x0>;
                        xlnx,pcw-en-modem-uart0 = <0x0>;
                        xlnx,pcw-en-modem-uart1 = <0x0>;
                        xlnx,pcw-trace-grp-16bit-enable = <0x0>;
                        xlnx,pcw-uiparam-ddr-freq-mhz = <0x1fca0555>;
                        xlnx,pcw-gp0-en-modifiable-txn = <0x1>;
                        xlnx,pcw-nor-sram-cs1-we-time = <0x0>;
                        xlnx,pcw-act-ttc0-clk2-peripheral-freqmhz = <0x69f6bcb>;
                        xlnx,pcw-uiparam-ddr-ecc = "Disabled";
                        xlnx,pcw-mio-25-iotype = "LVCMOS , 3.3V";
                        xlnx,pcw-act-pcap-peripheral-freqmhz = <0xc8>;
                        xlnx,pcw-uart1-grp-full-enable = <0x0>;
                        xlnx,pcw-ddr-peripheral-clksrc = "DDR , PLL";
                        xlnx,pcw-mio-19-direction = "inout";
                        xlnx,pcw-mio-20-direction = "inout";
                        xlnx,pcw-mio-12-pullup = "enabled";
                        xlnx,pcw-ddr-ram-highaddr = <0x1fffffff>;
                        xlnx,en-emio-trace = <0x0>;
                        xlnx,pcw-nor-sram-cs1-t-tr = <0x1>;
                        xlnx,pcw-nor-nor-io = "<Select>";
                        xlnx,pcw-s-axi-gp0-freqmhz = <0xa>;
                        xlnx,pcw-spi-peripheral-divisor0 = <0x1>;
                        xlnx,pcw-trace-buffer-clock-delay = <0xc>;
                        xlnx,pcw-uiparam-ddr-clock-1-package-length = <0x34090b8>;
                        xlnx,pcw-mio-5-iotype = "LVCMOS , 3.3V";
                        xlnx,pcw-mio-6-direction = "out";
                        xlnx,pcw-mio-42-iotype = "LVCMOS , 3.3V";
                        xlnx,pcw-s-axi-acp-awuser-val = <0x1f>;
                        xlnx,pcw-use-expanded-ps-slcr-registers = <0x0>;
                        xlnx,pcw-uiparam-ddr-cwl = <0x6>;
                        xlnx,pcw-spi1-peripheral-enable = <0x0>;
                        xlnx,pcw-nor-sram-cs1-t-wc = <0xb>;
                        xlnx,pcw-tpiu-peripheral-freqmhz = <0xc8>;
                        xlnx,pcw-pjtag-pjtag-io = "<Select>";
                        xlnx,pcw-wdt-peripheral-clksrc = "CPU_1X";
                        xlnx,pcw-uiparam-ddr-dq-2-propogation-delay = <0xa0>;
                        xlnx,pcw-uiparam-ddr-dqs-3-package-length = <0x447256c>;
                        xlnx,pcw-mio-28-pullup = "enabled";
                        xlnx,pcw-mio-29-direction = "inout";
                        xlnx,pcw-mio-30-direction = "inout";
                        xlnx,pcw-en-clktrig2-port = <0x0>;
                        xlnx,pcw-enet0-grp-mdio-enable = <0x0>;
                        xlnx,pcw-usb0-peripheral-freqmhz = <0x3c>;
                        xlnx,pcw-enet0-baseaddr = <0xe000b000>;
                        xlnx,pcw-nor-sram-cs1-t-wp = <0x1>;
                        xlnx,pcw-act-ttc-peripheral-freqmhz = <0x32>;
                        xlnx,pcw-act-sdio-peripheral-freqmhz = <0x64>;
                        xlnx,pcw-import-board-preset = "None";
                        xlnx,pcw-mio-16-iotype = "LVCMOS , 3.3V";
                        xlnx,pcw-mio-8-pullup = "disabled";
                        xlnx,pcw-enet0-enet0-io = "<Select>";
                        xlnx,pcw-mio-45-pullup = "enabled";
                        xlnx,pcw-mio-39-direction = "inout";
                        xlnx,pcw-mio-40-direction = "inout";
                        xlnx,pcw-uiparam-ddr-device-capacity = "4096 , MBits";
                        xlnx,pcw-uiparam-ddr-al = <0x0>;
                        xlnx,pcw-can-peripheral-divisor0 = <0x1>;
                        xlnx,pcw-can-peripheral-divisor1 = <0x1>;
                        xlnx,use-trace-data-edge-detector = <0x0>;
                        xlnx,pcw-ttc0-clk2-peripheral-clksrc = "CPU_1X";
                        xlnx,pcw-nor-cs1-t-ceoe = <0x1>;
                        xlnx,pcw-qspi-grp-io1-enable = <0x0>;
                        xlnx,s-axi-gp1-id-width = <0x6>;
                        xlnx,pcw-uiparam-ddr-bl = <0x8>;
                        xlnx,pcw-peripheral-board-preset = "None";
                        xlnx,pcw-en-emio-wp-sdio0 = <0x0>;
                        xlnx,pcw-p2f-usb1-intr = <0x0>;
                        xlnx,pcw-en-emio-wp-sdio1 = <0x0>;
                        xlnx,pcw-m-axi-gp1-freqmhz = <0xa>;
                        xlnx,pcw-p2f-spi0-intr = <0x0>;
                        xlnx,pcw-sd0-grp-pow-io = "<Select>";
                        xlnx,pcw-mio-33-iotype = "LVCMOS , 3.3V";
                        xlnx,pcw-uiparam-ddr-cl = <0x7>;
                        xlnx,pcw-ttc1-ttc1-io = "<Select>";
                        xlnx,pcw-en-smc = <0x0>;
                        xlnx,pcw-fclk-clk3-buf;
                        xlnx,pcw-mio-49-direction = "inout";
                        xlnx,pcw-mio-50-direction = "inout";
                        xlnx,pcw-enet0-reset-io = "<Select>";
                        xlnx,pcw-mio-8-slew = "slow";
                        xlnx,pcw-mio-19-pullup = "enabled";
                        xlnx,pcw-mio-20-pullup = "enabled";
                        xlnx,pcw-enet1-enet1-io = "<Select>";
                        xlnx,pcw-qspi-grp-ss1-io = "<Select>";
                        xlnx,pcw-en-i2c0 = <0x1>;
                        xlnx,pcw-dci-peripheral-divisor0 = <0xf>;
                        xlnx,pcw-en-i2c1 = <0x1>;
                        xlnx,pcw-dci-peripheral-divisor1 = <0x7>;
                        xlnx,pcw-mio-5-slew = "slow";
                        xlnx,s-axi-hp1-id-width = <0x6>;
                        xlnx,pcw-core0-fiq-intr = <0x0>;
                        xlnx,pcw-fclk1-peripheral-clksrc = "IO , PLL";
                        xlnx,pcw-act-ttc1-clk1-peripheral-freqmhz = <0x69f6bcb>;
                        xlnx,highaddr = <0x1fffffff>;
                        xlnx,pcw-mio-2-slew = "slow";
                        xlnx,pcw-en-qspi = <0x1>;
                        xlnx,pcw-mio-49-iotype = "LVCMOS , 3.3V";
                        xlnx,pcw-mio-50-iotype = "LVCMOS , 3.3V";
                        xlnx,pcw-sd1-grp-pow-io = "<Select>";
                        xlnx,pcw-en-uart0 = <0x0>;
                        xlnx,pcw-i2c1-peripheral-enable = <0x1>;
                        xlnx,pcw-en-uart1 = <0x0>;
                        xlnx,pcw-ddr-port0-hpr-enable = <0x0>;
                        xlnx,pcw-mio-0-pullup = "enabled";
                        xlnx,pcw-enet1-peripheral-enable = <0x0>;
                        xlnx,pcw-gpio-mio-gpio-io = "MIO";
                        xlnx,pcw-mio-36-pullup = "enabled";
                        xlnx,pcw-spi0-grp-ss0-io = "<Select>";
                        phandle = <0x46>;
                };

                ps7_pmu_0: ps7_pmu@f8891000 {
                        xlnx,rable = <0x0>;
                        xlnx,pmu1-s-axi-highaddr = <0xf8893fff>;
                        compatible = "xlnx,ps7-pmu-1.00.a";
                        status = "okay";
                        xlnx,ip-name = "ps7_pmu";
                        reg = <0xf8891000 0x1000 0xf8893000 0x1000>;
                        xlnx,pmu1-s-axi-baseaddr = <0xf8893000>;
                        xlnx,name = "ps7_pmu_0";
                        phandle = <0x17>;
                };

                ps7_qspi_linear_0: ps7_qspi_linear@fc000000 {
                        xlnx,rable = <0x0>;
                        compatible = "xlnx,ps7-qspi-linear-1.00.a";
                        status = "okay";
                        xlnx,interconnect-s-axi-masters = "ps7_cortexa9_0.M_AXI_DP , & , ps7_cortexa9_1.M_AXI_DP";
                        xlnx,ip-name = "ps7_qspi_linear";
                        reg = <0xfc000000 0x1000000>;
                        xlnx,name = "ps7_qspi_linear_0";
                        phandle = <0x19>;
                };

                ps7_ddr_0: ps7_ddr@100000 {
                        compatible = "xlnx,ps7-ddr-1.00.a";
                        xlnx,s-axi-hp1-baseaddr = <0xfffffff>;
                        xlnx,s-axi-hp3-baseaddr = <0xfffffff>;
                        xlnx,rable = <0x0>;
                        xlnx,ip-name = "ps7_ddr";
                        xlnx,interconnect-s-axi-masters = "ps7_cortexa9_0.M_AXI_DP , & , ps7_cortexa9_1.M_AXI_DP";
                        reg = <0x100000 0x1ff00000>;
                        xlnx,s-axi-hp1-highaddr = <0xfffffff>;
                        xlnx,s-axi-hp3-highaddr = <0xfffffff>;
                        xlnx,s-axi-hp0-baseaddr = <0xfffffff>;
                        xlnx,s-axi-hp2-baseaddr = <0xfffffff>;
                        status = "okay";
                        xlnx,s-axi-hp0-highaddr = <0xfffffff>;
                        xlnx,s-axi-hp2-highaddr = <0xfffffff>;
                        xlnx,name = "ps7_ddr_0";
                        phandle = <0x47>;
                };

                ps7_ocmc_0: ps7_ocmc@f800c000 {
                        xlnx,rable = <0x0>;
                        compatible = "xlnx,ps7-ocmc-1.00.a";
                        status = "okay";
                        xlnx,interconnect-s-axi-masters = "ps7_cortexa9_0.M_AXI_DP , & , ps7_cortexa9_1.M_AXI_DP";
                        xlnx,ip-name = "ps7_ocmc";
                        reg = <0xf800c000 0x1000>;
                        xlnx,name = "ps7_ocmc_0";
                        phandle = <0x16>;
                };

                ps7_gpv_0: ps7_gpv@f8900000 {
                        xlnx,rable = <0x0>;
                        compatible = "xlnx,ps7-gpv-1.00.a";
                        status = "okay";
                        xlnx,interconnect-s-axi-masters = "ps7_cortexa9_0.M_AXI_DP , & , ps7_cortexa9_1.M_AXI_DP";
                        xlnx,ip-name = "ps7_gpv";
                        reg = <0xf8900000 0x100000>;
                        xlnx,name = "ps7_gpv_0";
                        phandle = <0x10>;
                };

                ps7_scuc_0: ps7_scuc@f8f00000 {
                        xlnx,rable = <0x0>;
                        compatible = "xlnx,ps7-scuc-1.00.a";
                        status = "okay";
                        xlnx,interconnect-s-axi-masters = "ps7_cortexa9_0.M_AXI_DP , & , ps7_cortexa9_1.M_AXI_DP";
                        xlnx,ip-name = "ps7_scuc";
                        reg = <0xf8f00000 0xfd>;
                        xlnx,name = "ps7_scuc_0";
                        phandle = <0x1a>;
                };

                ps7_iop_bus_config_0: ps7_iop_bus_config@e0200000 {
                        xlnx,rable = <0x0>;
                        compatible = "xlnx,ps7-iop-bus-config-1.00.a";
                        status = "okay";
                        xlnx,interconnect-s-axi-masters = "ps7_cortexa9_0.M_AXI_DP , & , ps7_cortexa9_1.M_AXI_DP";
                        xlnx,ip-name = "ps7_iop_bus_config";
                        reg = <0xe0200000 0x1000>;
                        xlnx,name = "ps7_iop_bus_config_0";
                        phandle = <0x14>;
                };

                ps7_ram_0: ps7_ram@0 {
                        xlnx,rable = <0x0>;
                        compatible = "xlnx,ps7-ram-1.00.a";
                        status = "okay";
                        xlnx,interconnect-s-axi-masters = "ps7_cortexa9_0.M_AXI_DP , & , ps7_cortexa9_1.M_AXI_DP";
                        xlnx,ip-name = "ps7_ram";
                        reg = <0x0 0x30000>;
                        xlnx,name = "ps7_ram_0";
                        phandle = <0x48>;
                };

                ps7_ram_1: ps7_ram@ffff0000 {
                        xlnx,rable = <0x0>;
                        compatible = "xlnx,ps7-ram-1.00.a";
                        status = "okay";
                        xlnx,interconnect-s-axi-masters = "ps7_cortexa9_0.M_AXI_DP , & , ps7_cortexa9_1.M_AXI_DP";
                        xlnx,ip-name = "ps7_ram";
                        reg = <0xffff0000 0xfe00>;
                        xlnx,name = "ps7_ram_1";
                        phandle = <0x49>;
                };

                ps7_dma_ns: ps7_dma@f8004000 {
                        xlnx,rable = <0x0>;
                        compatible = "xlnx,ps7-dma-1.00.a";
                        status = "okay";
                        xlnx,interconnect-s-axi-masters = "ps7_cortexa9_0.M_AXI_DP , & , ps7_cortexa9_1.M_AXI_DP";
                        xlnx,ip-name = "ps7_dma";
                        xlnx,is-secure;
                        reg = <0xf8004000 0x1000>;
                        xlnx,name = "ps7_dma_ns";
                        phandle = <0xc>;
                };

                ps7_afi_0: ps7_afi@f8008000 {
                        xlnx,rable = <0x0>;
                        compatible = "xlnx,ps7-afi-1.00.a";
                        status = "okay";
                        xlnx,interconnect-s-axi-masters = "ps7_cortexa9_0.M_AXI_DP , & , ps7_cortexa9_1.M_AXI_DP";
                        xlnx,ip-name = "ps7_afi";
                        reg = <0xf8008000 0x1000>;
                        xlnx,name = "ps7_afi_0";
                        phandle = <0x5>;
                };

                ps7_afi_1: ps7_afi@f8009000 {
                        xlnx,rable = <0x0>;
                        compatible = "xlnx,ps7-afi-1.00.a";
                        status = "okay";
                        xlnx,interconnect-s-axi-masters = "ps7_cortexa9_0.M_AXI_DP , & , ps7_cortexa9_1.M_AXI_DP";
                        xlnx,ip-name = "ps7_afi";
                        reg = <0xf8009000 0x1000>;
                        xlnx,name = "ps7_afi_1";
                        phandle = <0x6>;
                };

                ps7_afi_2: ps7_afi@f800a000 {
                        xlnx,rable = <0x0>;
                        compatible = "xlnx,ps7-afi-1.00.a";
                        status = "okay";
                        xlnx,interconnect-s-axi-masters = "ps7_cortexa9_0.M_AXI_DP , & , ps7_cortexa9_1.M_AXI_DP";
                        xlnx,ip-name = "ps7_afi";
                        reg = <0xf800a000 0x1000>;
                        xlnx,name = "ps7_afi_2";
                        phandle = <0x7>;
                };

                ps7_afi_3: ps7_afi@f800b000 {
                        xlnx,rable = <0x0>;
                        compatible = "xlnx,ps7-afi-1.00.a";
                        status = "okay";
                        xlnx,interconnect-s-axi-masters = "ps7_cortexa9_0.M_AXI_DP , & , ps7_cortexa9_1.M_AXI_DP";
                        xlnx,ip-name = "ps7_afi";
                        reg = <0xf800b000 0x1000>;
                        xlnx,name = "ps7_afi_3";
                        phandle = <0x8>;
                };

                ps7_m_axi_gp0: ps7_m_axi_gp@40000000 {
                        xlnx,rable = <0x0>;
                        compatible = "xlnx,ps7-m-axi-gp-1.00.a";
                        status = "okay";
                        xlnx,interconnect-s-axi-masters = "ps7_cortexa9_0.M_AXI_DP , & , ps7_cortexa9_1.M_AXI_DP";
                        xlnx,ip-name = "ps7_m_axi_gp";
                        reg = <0x40000000 0x40000000>;
                        xlnx,name = "ps7_m_axi_gp0";
                        phandle = <0x4a>;
                };
        };

        amba_pl: amba_pl {
                phandle = <0x4b>;
        };

        ps7_ddr_0_memory: memory@00100000 {
                compatible = "xlnx,ps7-ddr-1.00.a";
                device_type = "memory";
                reg = <0x100000 0x1ff00000>;
                phandle = <0x2>;
        };

        ps7_ram_0_memory: memory@0 {
                compatible = "xlnx,ps7-ram-1.00.a";
                device_type = "memory";
                reg = <0x0 0x30000>;
                phandle = <0x3>;
        };

        ps7_ram_1_memory: memory@ffff0000 {
                compatible = "xlnx,ps7-ram-1.00.a";
                device_type = "memory";
                reg = <0xffff0000 0xfe00>;
                phandle = <0x4>;
        };

        chosen {
                stdout-path = "serial0:115200n8";
        };

        aliases {
                serial0 = "/axi/coresight@f8800000";
                spi0 = "/axi/spi@e000d000";
                i2c0 = "/axi/i2c@e0004000";
                i2c1 = "/axi/i2c@e0005000";
        };

        __symbols__ {
                cpus_a9 = "/cpus-a9@0";
                ps7_cortexa9_0 = "/cpus-a9@0/cpu@0";
                ps7_cortexa9_1 = "/cpus-a9@0/cpu@1";
                fpga_full = "/fpga-full";
                regulator_vccpint = "/fixedregulator";
                replicator_out_port0 = "/replicator/out-ports/port@0/endpoint";
                replicator_out_port1 = "/replicator/out-ports/port@1/endpoint";
                replicator_in_port0 = "/replicator/in-ports/port/endpoint";
                amba = "/axi";
                adc = "/axi/adc@f8007100";
                can0 = "/axi/can@e0008000";
                can1 = "/axi/can@e0009000";
                gpio0 = "/axi/gpio@e000a000";
                i2c0 = "/axi/i2c@e0004000";
                i2c1 = "/axi/i2c@e0005000";
                intc = "/axi/interrupt-controller@f8f01000";
                L2 = "/axi/cache-controller@f8f02000";
                mc = "/axi/memory-controller@f8006000";
                ocm = "/axi/sram@fffc0000";
                uart0 = "/axi/serial@e0000000";
                uart1 = "/axi/serial@e0001000";
                spi0 = "/axi/spi@e0006000";
                spi1 = "/axi/spi@e0007000";
                qspi = "/axi/spi@e000d000";
                gem0 = "/axi/ethernet@e000b000";
                gem1 = "/axi/ethernet@e000c000";
                smcc = "/axi/memory-controller@e000e000";
                nfc0 = "/axi/memory-controller@e000e000/nand-controller@0,0";
                nor0 = "/axi/memory-controller@e000e000/flash@1,0";
                sdhci0 = "/axi/mmc@e0100000";
                sdhci1 = "/axi/mmc@e0101000";
                slcr = "/axi/slcr@f8000000";
                clkc = "/axi/slcr@f8000000/clkc@100";
                rstc = "/axi/slcr@f8000000/rstc@200";
                pinctrl0 = "/axi/slcr@f8000000/pinctrl@700";
                dmac_s = "/axi/dma-controller@f8003000";
                devcfg = "/axi/devcfg@f8007000";
                efuse = "/axi/efuse@f800d000";
                global_timer = "/axi/timer@f8f00200";
                ttc0 = "/axi/timer@f8001000";
                ttc1 = "/axi/timer@f8002000";
                scutimer = "/axi/timer@f8f00600";
                scuwdt = "/axi/scuwatchdog@f8f00620";
                usb0 = "/axi/usb@e0002000";
                usb1 = "/axi/usb@e0003000";
                watchdog0 = "/axi/watchdog@f8005000";
                coresight = "/axi/coresight@f8800000";
                etb_in_port = "/axi/etb@f8801000/in-ports/port/endpoint";
                tpiu_in_port = "/axi/tpiu@f8803000/in-ports/port/endpoint";
                funnel_out_port = "/axi/funnel@f8804000/out-ports/port/endpoint";
                funnel0_in_port0 = "/axi/funnel@f8804000/in-ports/port@0/endpoint";
                funnel0_in_port1 = "/axi/funnel@f8804000/in-ports/port@1/endpoint";
                funnel0_in_port2 = "/axi/funnel@f8804000/in-ports/port@2/endpoint";
                ptm0_out_port = "/axi/ptm@f889c000/out-ports/port/endpoint";
                ptm1_out_port = "/axi/ptm@f889d000/out-ports/port/endpoint";
                processing_system7_0 = "/axi/processing_system7@0";
                ps7_pmu_0 = "/axi/ps7_pmu@f8891000";
                ps7_qspi_linear_0 = "/axi/ps7_qspi_linear@fc000000";
                ps7_ddr_0 = "/axi/ps7_ddr@100000";
                ps7_ocmc_0 = "/axi/ps7_ocmc@f800c000";
                ps7_gpv_0 = "/axi/ps7_gpv@f8900000";
                ps7_scuc_0 = "/axi/ps7_scuc@f8f00000";
                ps7_iop_bus_config_0 = "/axi/ps7_iop_bus_config@e0200000";
                ps7_ram_0 = "/axi/ps7_ram@0";
                ps7_ram_1 = "/axi/ps7_ram@ffff0000";
                ps7_dma_ns = "/axi/ps7_dma@f8004000";
                ps7_afi_0 = "/axi/ps7_afi@f8008000";
                ps7_afi_1 = "/axi/ps7_afi@f8009000";
                ps7_afi_2 = "/axi/ps7_afi@f800a000";
                ps7_afi_3 = "/axi/ps7_afi@f800b000";
                ps7_m_axi_gp0 = "/axi/ps7_m_axi_gp@40000000";
                amba_pl = "/amba_pl";
                ps7_ddr_0_memory = "/memory@00100000";
                ps7_ram_0_memory = "/memory@0";
                ps7_ram_1_memory = "/memory@ffff0000";
        };
};
